VERSION 5.8 ;
BUSBITCHARS "[]" ;
DIVIDERCHAR "/" ;
UNITS
    DATABASE MICRONS 1000 ;
END UNITS

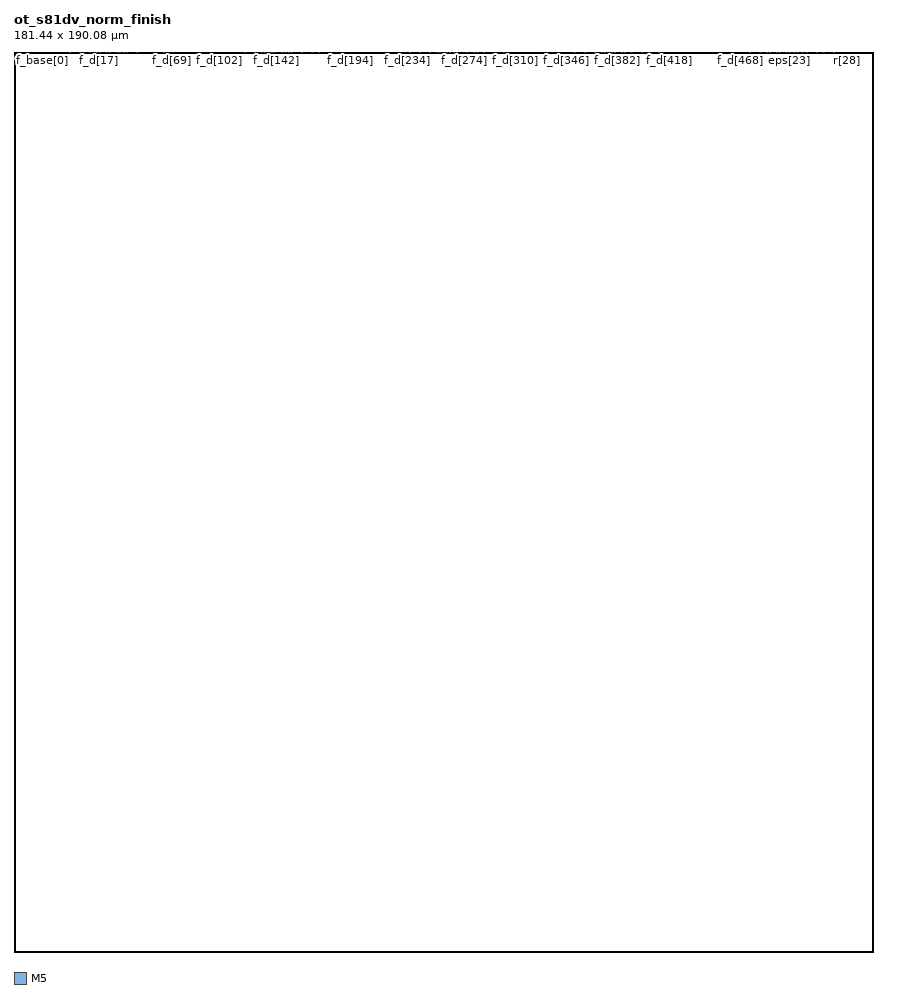
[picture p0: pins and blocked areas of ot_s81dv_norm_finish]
MACRO ot_s81dv_norm_finish
  FOREIGN ot_s81dv_norm_finish 0 0 ;
  CLASS BLOCK ;
  SIZE 181.44 BY 190.08 ;
  PIN go
    DIRECTION INPUT ;
    USE SIGNAL ;
    PORT
      LAYER M5 ;
        RECT 4.3200 189.9960 4.3440 190.0800 ;
    END
  END go
  PIN f_v[0]
    DIRECTION INPUT ;
    USE SIGNAL ;
    PORT
      LAYER M5 ;
        RECT 4.6080 189.9960 4.6320 190.0800 ;
    END
  END f_v[0]
  PIN f_v[1]
    DIRECTION INPUT ;
    USE SIGNAL ;
    PORT
      LAYER M5 ;
        RECT 4.9440 189.9960 4.9680 190.0800 ;
    END
  END f_v[1]
  PIN f_v[2]
    DIRECTION INPUT ;
    USE SIGNAL ;
    PORT
      LAYER M5 ;
        RECT 5.2320 189.9960 5.2560 190.0800 ;
    END
  END f_v[2]
  PIN f_base[0]
    DIRECTION INPUT ;
    USE SIGNAL ;
    PORT
      LAYER M5 ;
        RECT 5.5200 189.9960 5.5440 190.0800 ;
    END
  END f_base[0]
  PIN f_base[1]
    DIRECTION INPUT ;
    USE SIGNAL ;
    PORT
      LAYER M5 ;
        RECT 5.8080 189.9960 5.8320 190.0800 ;
    END
  END f_base[1]
  PIN f_base[2]
    DIRECTION INPUT ;
    USE SIGNAL ;
    PORT
      LAYER M5 ;
        RECT 6.1440 189.9960 6.1680 190.0800 ;
    END
  END f_base[2]
  PIN f_base[3]
    DIRECTION INPUT ;
    USE SIGNAL ;
    PORT
      LAYER M5 ;
        RECT 6.4320 189.9960 6.4560 190.0800 ;
    END
  END f_base[3]
  PIN f_base[4]
    DIRECTION INPUT ;
    USE SIGNAL ;
    PORT
      LAYER M5 ;
        RECT 6.7200 189.9960 6.7440 190.0800 ;
    END
  END f_base[4]
  PIN f_base[5]
    DIRECTION INPUT ;
    USE SIGNAL ;
    PORT
      LAYER M5 ;
        RECT 7.0080 189.9960 7.0320 190.0800 ;
    END
  END f_base[5]
  PIN f_base[6]
    DIRECTION INPUT ;
    USE SIGNAL ;
    PORT
      LAYER M5 ;
        RECT 7.3440 189.9960 7.3680 190.0800 ;
    END
  END f_base[6]
  PIN f_base[7]
    DIRECTION INPUT ;
    USE SIGNAL ;
    PORT
      LAYER M5 ;
        RECT 7.6320 189.9960 7.6560 190.0800 ;
    END
  END f_base[7]
  PIN f_base[8]
    DIRECTION INPUT ;
    USE SIGNAL ;
    PORT
      LAYER M5 ;
        RECT 7.9200 189.9960 7.9440 190.0800 ;
    END
  END f_base[8]
  PIN f_base[9]
    DIRECTION INPUT ;
    USE SIGNAL ;
    PORT
      LAYER M5 ;
        RECT 8.2080 189.9960 8.2320 190.0800 ;
    END
  END f_base[9]
  PIN f_base[10]
    DIRECTION INPUT ;
    USE SIGNAL ;
    PORT
      LAYER M5 ;
        RECT 8.5440 189.9960 8.5680 190.0800 ;
    END
  END f_base[10]
  PIN f_base[11]
    DIRECTION INPUT ;
    USE SIGNAL ;
    PORT
      LAYER M5 ;
        RECT 8.8320 189.9960 8.8560 190.0800 ;
    END
  END f_base[11]
  PIN f_base[12]
    DIRECTION INPUT ;
    USE SIGNAL ;
    PORT
      LAYER M5 ;
        RECT 9.1200 189.9960 9.1440 190.0800 ;
    END
  END f_base[12]
  PIN f_base[13]
    DIRECTION INPUT ;
    USE SIGNAL ;
    PORT
      LAYER M5 ;
        RECT 9.4080 189.9960 9.4320 190.0800 ;
    END
  END f_base[13]
  PIN f_base[14]
    DIRECTION INPUT ;
    USE SIGNAL ;
    PORT
      LAYER M5 ;
        RECT 9.7440 189.9960 9.7680 190.0800 ;
    END
  END f_base[14]
  PIN f_base[15]
    DIRECTION INPUT ;
    USE SIGNAL ;
    PORT
      LAYER M5 ;
        RECT 10.0320 189.9960 10.0560 190.0800 ;
    END
  END f_base[15]
  PIN f_base[16]
    DIRECTION INPUT ;
    USE SIGNAL ;
    PORT
      LAYER M5 ;
        RECT 10.3200 189.9960 10.3440 190.0800 ;
    END
  END f_base[16]
  PIN f_base[17]
    DIRECTION INPUT ;
    USE SIGNAL ;
    PORT
      LAYER M5 ;
        RECT 10.6080 189.9960 10.6320 190.0800 ;
    END
  END f_base[17]
  PIN f_base[18]
    DIRECTION INPUT ;
    USE SIGNAL ;
    PORT
      LAYER M5 ;
        RECT 10.9440 189.9960 10.9680 190.0800 ;
    END
  END f_base[18]
  PIN f_base[19]
    DIRECTION INPUT ;
    USE SIGNAL ;
    PORT
      LAYER M5 ;
        RECT 11.2320 189.9960 11.2560 190.0800 ;
    END
  END f_base[19]
  PIN f_base[20]
    DIRECTION INPUT ;
    USE SIGNAL ;
    PORT
      LAYER M5 ;
        RECT 11.5200 189.9960 11.5440 190.0800 ;
    END
  END f_base[20]
  PIN f_base[21]
    DIRECTION INPUT ;
    USE SIGNAL ;
    PORT
      LAYER M5 ;
        RECT 11.8080 189.9960 11.8320 190.0800 ;
    END
  END f_base[21]
  PIN f_base[22]
    DIRECTION INPUT ;
    USE SIGNAL ;
    PORT
      LAYER M5 ;
        RECT 12.1440 189.9960 12.1680 190.0800 ;
    END
  END f_base[22]
  PIN f_base[23]
    DIRECTION INPUT ;
    USE SIGNAL ;
    PORT
      LAYER M5 ;
        RECT 12.4320 189.9960 12.4560 190.0800 ;
    END
  END f_base[23]
  PIN f_d[0]
    DIRECTION INPUT ;
    USE SIGNAL ;
    PORT
      LAYER M5 ;
        RECT 12.7200 189.9960 12.7440 190.0800 ;
    END
  END f_d[0]
  PIN f_d[1]
    DIRECTION INPUT ;
    USE SIGNAL ;
    PORT
      LAYER M5 ;
        RECT 13.0560 189.9960 13.0800 190.0800 ;
    END
  END f_d[1]
  PIN f_d[2]
    DIRECTION INPUT ;
    USE SIGNAL ;
    PORT
      LAYER M5 ;
        RECT 13.3440 189.9960 13.3680 190.0800 ;
    END
  END f_d[2]
  PIN f_d[3]
    DIRECTION INPUT ;
    USE SIGNAL ;
    PORT
      LAYER M5 ;
        RECT 13.6320 189.9960 13.6560 190.0800 ;
    END
  END f_d[3]
  PIN f_d[4]
    DIRECTION INPUT ;
    USE SIGNAL ;
    PORT
      LAYER M5 ;
        RECT 13.9200 189.9960 13.9440 190.0800 ;
    END
  END f_d[4]
  PIN f_d[5]
    DIRECTION INPUT ;
    USE SIGNAL ;
    PORT
      LAYER M5 ;
        RECT 14.2560 189.9960 14.2800 190.0800 ;
    END
  END f_d[5]
  PIN f_d[6]
    DIRECTION INPUT ;
    USE SIGNAL ;
    PORT
      LAYER M5 ;
        RECT 14.5440 189.9960 14.5680 190.0800 ;
    END
  END f_d[6]
  PIN f_d[7]
    DIRECTION INPUT ;
    USE SIGNAL ;
    PORT
      LAYER M5 ;
        RECT 14.8320 189.9960 14.8560 190.0800 ;
    END
  END f_d[7]
  PIN f_d[8]
    DIRECTION INPUT ;
    USE SIGNAL ;
    PORT
      LAYER M5 ;
        RECT 15.1200 189.9960 15.1440 190.0800 ;
    END
  END f_d[8]
  PIN f_d[9]
    DIRECTION INPUT ;
    USE SIGNAL ;
    PORT
      LAYER M5 ;
        RECT 15.4560 189.9960 15.4800 190.0800 ;
    END
  END f_d[9]
  PIN f_d[10]
    DIRECTION INPUT ;
    USE SIGNAL ;
    PORT
      LAYER M5 ;
        RECT 15.7440 189.9960 15.7680 190.0800 ;
    END
  END f_d[10]
  PIN f_d[11]
    DIRECTION INPUT ;
    USE SIGNAL ;
    PORT
      LAYER M5 ;
        RECT 16.0320 189.9960 16.0560 190.0800 ;
    END
  END f_d[11]
  PIN f_d[12]
    DIRECTION INPUT ;
    USE SIGNAL ;
    PORT
      LAYER M5 ;
        RECT 16.3200 189.9960 16.3440 190.0800 ;
    END
  END f_d[12]
  PIN f_d[13]
    DIRECTION INPUT ;
    USE SIGNAL ;
    PORT
      LAYER M5 ;
        RECT 16.6560 189.9960 16.6800 190.0800 ;
    END
  END f_d[13]
  PIN f_d[14]
    DIRECTION INPUT ;
    USE SIGNAL ;
    PORT
      LAYER M5 ;
        RECT 16.9440 189.9960 16.9680 190.0800 ;
    END
  END f_d[14]
  PIN f_d[15]
    DIRECTION INPUT ;
    USE SIGNAL ;
    PORT
      LAYER M5 ;
        RECT 17.2320 189.9960 17.2560 190.0800 ;
    END
  END f_d[15]
  PIN f_d[16]
    DIRECTION INPUT ;
    USE SIGNAL ;
    PORT
      LAYER M5 ;
        RECT 17.5200 189.9960 17.5440 190.0800 ;
    END
  END f_d[16]
  PIN f_d[17]
    DIRECTION INPUT ;
    USE SIGNAL ;
    PORT
      LAYER M5 ;
        RECT 17.8560 189.9960 17.8800 190.0800 ;
    END
  END f_d[17]
  PIN f_d[18]
    DIRECTION INPUT ;
    USE SIGNAL ;
    PORT
      LAYER M5 ;
        RECT 18.1440 189.9960 18.1680 190.0800 ;
    END
  END f_d[18]
  PIN f_d[19]
    DIRECTION INPUT ;
    USE SIGNAL ;
    PORT
      LAYER M5 ;
        RECT 18.4320 189.9960 18.4560 190.0800 ;
    END
  END f_d[19]
  PIN f_d[20]
    DIRECTION INPUT ;
    USE SIGNAL ;
    PORT
      LAYER M5 ;
        RECT 18.7200 189.9960 18.7440 190.0800 ;
    END
  END f_d[20]
  PIN f_d[21]
    DIRECTION INPUT ;
    USE SIGNAL ;
    PORT
      LAYER M5 ;
        RECT 19.0560 189.9960 19.0800 190.0800 ;
    END
  END f_d[21]
  PIN f_d[22]
    DIRECTION INPUT ;
    USE SIGNAL ;
    PORT
      LAYER M5 ;
        RECT 19.3440 189.9960 19.3680 190.0800 ;
    END
  END f_d[22]
  PIN f_d[23]
    DIRECTION INPUT ;
    USE SIGNAL ;
    PORT
      LAYER M5 ;
        RECT 19.6320 189.9960 19.6560 190.0800 ;
    END
  END f_d[23]
  PIN f_d[24]
    DIRECTION INPUT ;
    USE SIGNAL ;
    PORT
      LAYER M5 ;
        RECT 19.9200 189.9960 19.9440 190.0800 ;
    END
  END f_d[24]
  PIN f_d[25]
    DIRECTION INPUT ;
    USE SIGNAL ;
    PORT
      LAYER M5 ;
        RECT 20.2560 189.9960 20.2800 190.0800 ;
    END
  END f_d[25]
  PIN f_d[26]
    DIRECTION INPUT ;
    USE SIGNAL ;
    PORT
      LAYER M5 ;
        RECT 20.5440 189.9960 20.5680 190.0800 ;
    END
  END f_d[26]
  PIN f_d[27]
    DIRECTION INPUT ;
    USE SIGNAL ;
    PORT
      LAYER M5 ;
        RECT 20.8320 189.9960 20.8560 190.0800 ;
    END
  END f_d[27]
  PIN f_d[28]
    DIRECTION INPUT ;
    USE SIGNAL ;
    PORT
      LAYER M5 ;
        RECT 21.1680 189.9960 21.1920 190.0800 ;
    END
  END f_d[28]
  PIN f_d[29]
    DIRECTION INPUT ;
    USE SIGNAL ;
    PORT
      LAYER M5 ;
        RECT 21.4560 189.9960 21.4800 190.0800 ;
    END
  END f_d[29]
  PIN f_d[30]
    DIRECTION INPUT ;
    USE SIGNAL ;
    PORT
      LAYER M5 ;
        RECT 21.7440 189.9960 21.7680 190.0800 ;
    END
  END f_d[30]
  PIN f_d[31]
    DIRECTION INPUT ;
    USE SIGNAL ;
    PORT
      LAYER M5 ;
        RECT 22.0320 189.9960 22.0560 190.0800 ;
    END
  END f_d[31]
  PIN f_d[32]
    DIRECTION INPUT ;
    USE SIGNAL ;
    PORT
      LAYER M5 ;
        RECT 22.3680 189.9960 22.3920 190.0800 ;
    END
  END f_d[32]
  PIN f_d[33]
    DIRECTION INPUT ;
    USE SIGNAL ;
    PORT
      LAYER M5 ;
        RECT 22.6560 189.9960 22.6800 190.0800 ;
    END
  END f_d[33]
  PIN f_d[34]
    DIRECTION INPUT ;
    USE SIGNAL ;
    PORT
      LAYER M5 ;
        RECT 22.9440 189.9960 22.9680 190.0800 ;
    END
  END f_d[34]
  PIN f_d[35]
    DIRECTION INPUT ;
    USE SIGNAL ;
    PORT
      LAYER M5 ;
        RECT 23.2320 189.9960 23.2560 190.0800 ;
    END
  END f_d[35]
  PIN f_d[36]
    DIRECTION INPUT ;
    USE SIGNAL ;
    PORT
      LAYER M5 ;
        RECT 23.5680 189.9960 23.5920 190.0800 ;
    END
  END f_d[36]
  PIN f_d[37]
    DIRECTION INPUT ;
    USE SIGNAL ;
    PORT
      LAYER M5 ;
        RECT 23.8560 189.9960 23.8800 190.0800 ;
    END
  END f_d[37]
  PIN f_d[38]
    DIRECTION INPUT ;
    USE SIGNAL ;
    PORT
      LAYER M5 ;
        RECT 24.1440 189.9960 24.1680 190.0800 ;
    END
  END f_d[38]
  PIN f_d[39]
    DIRECTION INPUT ;
    USE SIGNAL ;
    PORT
      LAYER M5 ;
        RECT 24.4320 189.9960 24.4560 190.0800 ;
    END
  END f_d[39]
  PIN f_d[40]
    DIRECTION INPUT ;
    USE SIGNAL ;
    PORT
      LAYER M5 ;
        RECT 24.7680 189.9960 24.7920 190.0800 ;
    END
  END f_d[40]
  PIN f_d[41]
    DIRECTION INPUT ;
    USE SIGNAL ;
    PORT
      LAYER M5 ;
        RECT 25.0560 189.9960 25.0800 190.0800 ;
    END
  END f_d[41]
  PIN f_d[42]
    DIRECTION INPUT ;
    USE SIGNAL ;
    PORT
      LAYER M5 ;
        RECT 25.3440 189.9960 25.3680 190.0800 ;
    END
  END f_d[42]
  PIN f_d[43]
    DIRECTION INPUT ;
    USE SIGNAL ;
    PORT
      LAYER M5 ;
        RECT 25.6320 189.9960 25.6560 190.0800 ;
    END
  END f_d[43]
  PIN f_d[44]
    DIRECTION INPUT ;
    USE SIGNAL ;
    PORT
      LAYER M5 ;
        RECT 25.9680 189.9960 25.9920 190.0800 ;
    END
  END f_d[44]
  PIN f_d[45]
    DIRECTION INPUT ;
    USE SIGNAL ;
    PORT
      LAYER M5 ;
        RECT 26.2560 189.9960 26.2800 190.0800 ;
    END
  END f_d[45]
  PIN f_d[46]
    DIRECTION INPUT ;
    USE SIGNAL ;
    PORT
      LAYER M5 ;
        RECT 26.5440 189.9960 26.5680 190.0800 ;
    END
  END f_d[46]
  PIN f_d[47]
    DIRECTION INPUT ;
    USE SIGNAL ;
    PORT
      LAYER M5 ;
        RECT 26.8320 189.9960 26.8560 190.0800 ;
    END
  END f_d[47]
  PIN f_d[48]
    DIRECTION INPUT ;
    USE SIGNAL ;
    PORT
      LAYER M5 ;
        RECT 27.1680 189.9960 27.1920 190.0800 ;
    END
  END f_d[48]
  PIN f_d[49]
    DIRECTION INPUT ;
    USE SIGNAL ;
    PORT
      LAYER M5 ;
        RECT 27.4560 189.9960 27.4800 190.0800 ;
    END
  END f_d[49]
  PIN f_d[50]
    DIRECTION INPUT ;
    USE SIGNAL ;
    PORT
      LAYER M5 ;
        RECT 27.7440 189.9960 27.7680 190.0800 ;
    END
  END f_d[50]
  PIN f_d[51]
    DIRECTION INPUT ;
    USE SIGNAL ;
    PORT
      LAYER M5 ;
        RECT 28.0320 189.9960 28.0560 190.0800 ;
    END
  END f_d[51]
  PIN f_d[52]
    DIRECTION INPUT ;
    USE SIGNAL ;
    PORT
      LAYER M5 ;
        RECT 28.3680 189.9960 28.3920 190.0800 ;
    END
  END f_d[52]
  PIN f_d[53]
    DIRECTION INPUT ;
    USE SIGNAL ;
    PORT
      LAYER M5 ;
        RECT 28.6560 189.9960 28.6800 190.0800 ;
    END
  END f_d[53]
  PIN f_d[54]
    DIRECTION INPUT ;
    USE SIGNAL ;
    PORT
      LAYER M5 ;
        RECT 28.9440 189.9960 28.9680 190.0800 ;
    END
  END f_d[54]
  PIN f_d[55]
    DIRECTION INPUT ;
    USE SIGNAL ;
    PORT
      LAYER M5 ;
        RECT 29.2800 189.9960 29.3040 190.0800 ;
    END
  END f_d[55]
  PIN f_d[56]
    DIRECTION INPUT ;
    USE SIGNAL ;
    PORT
      LAYER M5 ;
        RECT 29.5680 189.9960 29.5920 190.0800 ;
    END
  END f_d[56]
  PIN f_d[57]
    DIRECTION INPUT ;
    USE SIGNAL ;
    PORT
      LAYER M5 ;
        RECT 29.8560 189.9960 29.8800 190.0800 ;
    END
  END f_d[57]
  PIN f_d[58]
    DIRECTION INPUT ;
    USE SIGNAL ;
    PORT
      LAYER M5 ;
        RECT 30.1440 189.9960 30.1680 190.0800 ;
    END
  END f_d[58]
  PIN f_d[59]
    DIRECTION INPUT ;
    USE SIGNAL ;
    PORT
      LAYER M5 ;
        RECT 30.4800 189.9960 30.5040 190.0800 ;
    END
  END f_d[59]
  PIN f_d[60]
    DIRECTION INPUT ;
    USE SIGNAL ;
    PORT
      LAYER M5 ;
        RECT 30.7680 189.9960 30.7920 190.0800 ;
    END
  END f_d[60]
  PIN f_d[61]
    DIRECTION INPUT ;
    USE SIGNAL ;
    PORT
      LAYER M5 ;
        RECT 31.0560 189.9960 31.0800 190.0800 ;
    END
  END f_d[61]
  PIN f_d[62]
    DIRECTION INPUT ;
    USE SIGNAL ;
    PORT
      LAYER M5 ;
        RECT 31.3440 189.9960 31.3680 190.0800 ;
    END
  END f_d[62]
  PIN f_d[63]
    DIRECTION INPUT ;
    USE SIGNAL ;
    PORT
      LAYER M5 ;
        RECT 31.6800 189.9960 31.7040 190.0800 ;
    END
  END f_d[63]
  PIN f_d[64]
    DIRECTION INPUT ;
    USE SIGNAL ;
    PORT
      LAYER M5 ;
        RECT 31.9680 189.9960 31.9920 190.0800 ;
    END
  END f_d[64]
  PIN f_d[65]
    DIRECTION INPUT ;
    USE SIGNAL ;
    PORT
      LAYER M5 ;
        RECT 32.2560 189.9960 32.2800 190.0800 ;
    END
  END f_d[65]
  PIN f_d[66]
    DIRECTION INPUT ;
    USE SIGNAL ;
    PORT
      LAYER M5 ;
        RECT 32.5440 189.9960 32.5680 190.0800 ;
    END
  END f_d[66]
  PIN f_d[67]
    DIRECTION INPUT ;
    USE SIGNAL ;
    PORT
      LAYER M5 ;
        RECT 32.8800 189.9960 32.9040 190.0800 ;
    END
  END f_d[67]
  PIN f_d[68]
    DIRECTION INPUT ;
    USE SIGNAL ;
    PORT
      LAYER M5 ;
        RECT 33.1680 189.9960 33.1920 190.0800 ;
    END
  END f_d[68]
  PIN f_d[69]
    DIRECTION INPUT ;
    USE SIGNAL ;
    PORT
      LAYER M5 ;
        RECT 33.4560 189.9960 33.4800 190.0800 ;
    END
  END f_d[69]
  PIN f_d[70]
    DIRECTION INPUT ;
    USE SIGNAL ;
    PORT
      LAYER M5 ;
        RECT 33.7440 189.9960 33.7680 190.0800 ;
    END
  END f_d[70]
  PIN f_d[71]
    DIRECTION INPUT ;
    USE SIGNAL ;
    PORT
      LAYER M5 ;
        RECT 34.0800 189.9960 34.1040 190.0800 ;
    END
  END f_d[71]
  PIN f_d[72]
    DIRECTION INPUT ;
    USE SIGNAL ;
    PORT
      LAYER M5 ;
        RECT 34.3680 189.9960 34.3920 190.0800 ;
    END
  END f_d[72]
  PIN f_d[73]
    DIRECTION INPUT ;
    USE SIGNAL ;
    PORT
      LAYER M5 ;
        RECT 34.6560 189.9960 34.6800 190.0800 ;
    END
  END f_d[73]
  PIN f_d[74]
    DIRECTION INPUT ;
    USE SIGNAL ;
    PORT
      LAYER M5 ;
        RECT 34.9440 189.9960 34.9680 190.0800 ;
    END
  END f_d[74]
  PIN f_d[75]
    DIRECTION INPUT ;
    USE SIGNAL ;
    PORT
      LAYER M5 ;
        RECT 35.2800 189.9960 35.3040 190.0800 ;
    END
  END f_d[75]
  PIN f_d[76]
    DIRECTION INPUT ;
    USE SIGNAL ;
    PORT
      LAYER M5 ;
        RECT 35.5680 189.9960 35.5920 190.0800 ;
    END
  END f_d[76]
  PIN f_d[77]
    DIRECTION INPUT ;
    USE SIGNAL ;
    PORT
      LAYER M5 ;
        RECT 35.8560 189.9960 35.8800 190.0800 ;
    END
  END f_d[77]
  PIN f_d[78]
    DIRECTION INPUT ;
    USE SIGNAL ;
    PORT
      LAYER M5 ;
        RECT 36.1440 189.9960 36.1680 190.0800 ;
    END
  END f_d[78]
  PIN f_d[79]
    DIRECTION INPUT ;
    USE SIGNAL ;
    PORT
      LAYER M5 ;
        RECT 36.4800 189.9960 36.5040 190.0800 ;
    END
  END f_d[79]
  PIN f_d[80]
    DIRECTION INPUT ;
    USE SIGNAL ;
    PORT
      LAYER M5 ;
        RECT 36.7680 189.9960 36.7920 190.0800 ;
    END
  END f_d[80]
  PIN f_d[81]
    DIRECTION INPUT ;
    USE SIGNAL ;
    PORT
      LAYER M5 ;
        RECT 37.0560 189.9960 37.0800 190.0800 ;
    END
  END f_d[81]
  PIN f_d[82]
    DIRECTION INPUT ;
    USE SIGNAL ;
    PORT
      LAYER M5 ;
        RECT 37.3920 189.9960 37.4160 190.0800 ;
    END
  END f_d[82]
  PIN f_d[83]
    DIRECTION INPUT ;
    USE SIGNAL ;
    PORT
      LAYER M5 ;
        RECT 37.6800 189.9960 37.7040 190.0800 ;
    END
  END f_d[83]
  PIN f_d[84]
    DIRECTION INPUT ;
    USE SIGNAL ;
    PORT
      LAYER M5 ;
        RECT 37.9680 189.9960 37.9920 190.0800 ;
    END
  END f_d[84]
  PIN f_d[85]
    DIRECTION INPUT ;
    USE SIGNAL ;
    PORT
      LAYER M5 ;
        RECT 38.2560 189.9960 38.2800 190.0800 ;
    END
  END f_d[85]
  PIN f_d[86]
    DIRECTION INPUT ;
    USE SIGNAL ;
    PORT
      LAYER M5 ;
        RECT 38.5920 189.9960 38.6160 190.0800 ;
    END
  END f_d[86]
  PIN f_d[87]
    DIRECTION INPUT ;
    USE SIGNAL ;
    PORT
      LAYER M5 ;
        RECT 38.8800 189.9960 38.9040 190.0800 ;
    END
  END f_d[87]
  PIN f_d[88]
    DIRECTION INPUT ;
    USE SIGNAL ;
    PORT
      LAYER M5 ;
        RECT 39.1680 189.9960 39.1920 190.0800 ;
    END
  END f_d[88]
  PIN f_d[89]
    DIRECTION INPUT ;
    USE SIGNAL ;
    PORT
      LAYER M5 ;
        RECT 39.4560 189.9960 39.4800 190.0800 ;
    END
  END f_d[89]
  PIN f_d[90]
    DIRECTION INPUT ;
    USE SIGNAL ;
    PORT
      LAYER M5 ;
        RECT 39.7920 189.9960 39.8160 190.0800 ;
    END
  END f_d[90]
  PIN f_d[91]
    DIRECTION INPUT ;
    USE SIGNAL ;
    PORT
      LAYER M5 ;
        RECT 40.0800 189.9960 40.1040 190.0800 ;
    END
  END f_d[91]
  PIN f_d[92]
    DIRECTION INPUT ;
    USE SIGNAL ;
    PORT
      LAYER M5 ;
        RECT 40.3680 189.9960 40.3920 190.0800 ;
    END
  END f_d[92]
  PIN f_d[93]
    DIRECTION INPUT ;
    USE SIGNAL ;
    PORT
      LAYER M5 ;
        RECT 40.6560 189.9960 40.6800 190.0800 ;
    END
  END f_d[93]
  PIN f_d[94]
    DIRECTION INPUT ;
    USE SIGNAL ;
    PORT
      LAYER M5 ;
        RECT 40.9920 189.9960 41.0160 190.0800 ;
    END
  END f_d[94]
  PIN f_d[95]
    DIRECTION INPUT ;
    USE SIGNAL ;
    PORT
      LAYER M5 ;
        RECT 41.2800 189.9960 41.3040 190.0800 ;
    END
  END f_d[95]
  PIN f_d[96]
    DIRECTION INPUT ;
    USE SIGNAL ;
    PORT
      LAYER M5 ;
        RECT 41.5680 189.9960 41.5920 190.0800 ;
    END
  END f_d[96]
  PIN f_d[97]
    DIRECTION INPUT ;
    USE SIGNAL ;
    PORT
      LAYER M5 ;
        RECT 41.8560 189.9960 41.8800 190.0800 ;
    END
  END f_d[97]
  PIN f_d[98]
    DIRECTION INPUT ;
    USE SIGNAL ;
    PORT
      LAYER M5 ;
        RECT 42.1920 189.9960 42.2160 190.0800 ;
    END
  END f_d[98]
  PIN f_d[99]
    DIRECTION INPUT ;
    USE SIGNAL ;
    PORT
      LAYER M5 ;
        RECT 42.4800 189.9960 42.5040 190.0800 ;
    END
  END f_d[99]
  PIN f_d[100]
    DIRECTION INPUT ;
    USE SIGNAL ;
    PORT
      LAYER M5 ;
        RECT 42.7680 189.9960 42.7920 190.0800 ;
    END
  END f_d[100]
  PIN f_d[101]
    DIRECTION INPUT ;
    USE SIGNAL ;
    PORT
      LAYER M5 ;
        RECT 43.0560 189.9960 43.0800 190.0800 ;
    END
  END f_d[101]
  PIN f_d[102]
    DIRECTION INPUT ;
    USE SIGNAL ;
    PORT
      LAYER M5 ;
        RECT 43.3920 189.9960 43.4160 190.0800 ;
    END
  END f_d[102]
  PIN f_d[103]
    DIRECTION INPUT ;
    USE SIGNAL ;
    PORT
      LAYER M5 ;
        RECT 43.6800 189.9960 43.7040 190.0800 ;
    END
  END f_d[103]
  PIN f_d[104]
    DIRECTION INPUT ;
    USE SIGNAL ;
    PORT
      LAYER M5 ;
        RECT 43.9680 189.9960 43.9920 190.0800 ;
    END
  END f_d[104]
  PIN f_d[105]
    DIRECTION INPUT ;
    USE SIGNAL ;
    PORT
      LAYER M5 ;
        RECT 44.2560 189.9960 44.2800 190.0800 ;
    END
  END f_d[105]
  PIN f_d[106]
    DIRECTION INPUT ;
    USE SIGNAL ;
    PORT
      LAYER M5 ;
        RECT 44.5920 189.9960 44.6160 190.0800 ;
    END
  END f_d[106]
  PIN f_d[107]
    DIRECTION INPUT ;
    USE SIGNAL ;
    PORT
      LAYER M5 ;
        RECT 44.8800 189.9960 44.9040 190.0800 ;
    END
  END f_d[107]
  PIN f_d[108]
    DIRECTION INPUT ;
    USE SIGNAL ;
    PORT
      LAYER M5 ;
        RECT 45.1680 189.9960 45.1920 190.0800 ;
    END
  END f_d[108]
  PIN f_d[109]
    DIRECTION INPUT ;
    USE SIGNAL ;
    PORT
      LAYER M5 ;
        RECT 45.5040 189.9960 45.5280 190.0800 ;
    END
  END f_d[109]
  PIN f_d[110]
    DIRECTION INPUT ;
    USE SIGNAL ;
    PORT
      LAYER M5 ;
        RECT 45.7920 189.9960 45.8160 190.0800 ;
    END
  END f_d[110]
  PIN f_d[111]
    DIRECTION INPUT ;
    USE SIGNAL ;
    PORT
      LAYER M5 ;
        RECT 46.0800 189.9960 46.1040 190.0800 ;
    END
  END f_d[111]
  PIN f_d[112]
    DIRECTION INPUT ;
    USE SIGNAL ;
    PORT
      LAYER M5 ;
        RECT 46.3680 189.9960 46.3920 190.0800 ;
    END
  END f_d[112]
  PIN f_d[113]
    DIRECTION INPUT ;
    USE SIGNAL ;
    PORT
      LAYER M5 ;
        RECT 46.7040 189.9960 46.7280 190.0800 ;
    END
  END f_d[113]
  PIN f_d[114]
    DIRECTION INPUT ;
    USE SIGNAL ;
    PORT
      LAYER M5 ;
        RECT 46.9920 189.9960 47.0160 190.0800 ;
    END
  END f_d[114]
  PIN f_d[115]
    DIRECTION INPUT ;
    USE SIGNAL ;
    PORT
      LAYER M5 ;
        RECT 47.2800 189.9960 47.3040 190.0800 ;
    END
  END f_d[115]
  PIN f_d[116]
    DIRECTION INPUT ;
    USE SIGNAL ;
    PORT
      LAYER M5 ;
        RECT 47.5680 189.9960 47.5920 190.0800 ;
    END
  END f_d[116]
  PIN f_d[117]
    DIRECTION INPUT ;
    USE SIGNAL ;
    PORT
      LAYER M5 ;
        RECT 47.9040 189.9960 47.9280 190.0800 ;
    END
  END f_d[117]
  PIN f_d[118]
    DIRECTION INPUT ;
    USE SIGNAL ;
    PORT
      LAYER M5 ;
        RECT 48.1920 189.9960 48.2160 190.0800 ;
    END
  END f_d[118]
  PIN f_d[119]
    DIRECTION INPUT ;
    USE SIGNAL ;
    PORT
      LAYER M5 ;
        RECT 48.4800 189.9960 48.5040 190.0800 ;
    END
  END f_d[119]
  PIN f_d[120]
    DIRECTION INPUT ;
    USE SIGNAL ;
    PORT
      LAYER M5 ;
        RECT 48.7680 189.9960 48.7920 190.0800 ;
    END
  END f_d[120]
  PIN f_d[121]
    DIRECTION INPUT ;
    USE SIGNAL ;
    PORT
      LAYER M5 ;
        RECT 49.1040 189.9960 49.1280 190.0800 ;
    END
  END f_d[121]
  PIN f_d[122]
    DIRECTION INPUT ;
    USE SIGNAL ;
    PORT
      LAYER M5 ;
        RECT 49.3920 189.9960 49.4160 190.0800 ;
    END
  END f_d[122]
  PIN f_d[123]
    DIRECTION INPUT ;
    USE SIGNAL ;
    PORT
      LAYER M5 ;
        RECT 49.6800 189.9960 49.7040 190.0800 ;
    END
  END f_d[123]
  PIN f_d[124]
    DIRECTION INPUT ;
    USE SIGNAL ;
    PORT
      LAYER M5 ;
        RECT 49.9680 189.9960 49.9920 190.0800 ;
    END
  END f_d[124]
  PIN f_d[125]
    DIRECTION INPUT ;
    USE SIGNAL ;
    PORT
      LAYER M5 ;
        RECT 50.3040 189.9960 50.3280 190.0800 ;
    END
  END f_d[125]
  PIN f_d[126]
    DIRECTION INPUT ;
    USE SIGNAL ;
    PORT
      LAYER M5 ;
        RECT 50.5920 189.9960 50.6160 190.0800 ;
    END
  END f_d[126]
  PIN f_d[127]
    DIRECTION INPUT ;
    USE SIGNAL ;
    PORT
      LAYER M5 ;
        RECT 50.8800 189.9960 50.9040 190.0800 ;
    END
  END f_d[127]
  PIN f_d[128]
    DIRECTION INPUT ;
    USE SIGNAL ;
    PORT
      LAYER M5 ;
        RECT 51.1680 189.9960 51.1920 190.0800 ;
    END
  END f_d[128]
  PIN f_d[129]
    DIRECTION INPUT ;
    USE SIGNAL ;
    PORT
      LAYER M5 ;
        RECT 51.5040 189.9960 51.5280 190.0800 ;
    END
  END f_d[129]
  PIN f_d[130]
    DIRECTION INPUT ;
    USE SIGNAL ;
    PORT
      LAYER M5 ;
        RECT 51.7920 189.9960 51.8160 190.0800 ;
    END
  END f_d[130]
  PIN f_d[131]
    DIRECTION INPUT ;
    USE SIGNAL ;
    PORT
      LAYER M5 ;
        RECT 52.0800 189.9960 52.1040 190.0800 ;
    END
  END f_d[131]
  PIN f_d[132]
    DIRECTION INPUT ;
    USE SIGNAL ;
    PORT
      LAYER M5 ;
        RECT 52.3680 189.9960 52.3920 190.0800 ;
    END
  END f_d[132]
  PIN f_d[133]
    DIRECTION INPUT ;
    USE SIGNAL ;
    PORT
      LAYER M5 ;
        RECT 52.7040 189.9960 52.7280 190.0800 ;
    END
  END f_d[133]
  PIN f_d[134]
    DIRECTION INPUT ;
    USE SIGNAL ;
    PORT
      LAYER M5 ;
        RECT 52.9920 189.9960 53.0160 190.0800 ;
    END
  END f_d[134]
  PIN f_d[135]
    DIRECTION INPUT ;
    USE SIGNAL ;
    PORT
      LAYER M5 ;
        RECT 53.2800 189.9960 53.3040 190.0800 ;
    END
  END f_d[135]
  PIN f_d[136]
    DIRECTION INPUT ;
    USE SIGNAL ;
    PORT
      LAYER M5 ;
        RECT 53.5680 189.9960 53.5920 190.0800 ;
    END
  END f_d[136]
  PIN f_d[137]
    DIRECTION INPUT ;
    USE SIGNAL ;
    PORT
      LAYER M5 ;
        RECT 53.9040 189.9960 53.9280 190.0800 ;
    END
  END f_d[137]
  PIN f_d[138]
    DIRECTION INPUT ;
    USE SIGNAL ;
    PORT
      LAYER M5 ;
        RECT 54.1920 189.9960 54.2160 190.0800 ;
    END
  END f_d[138]
  PIN f_d[139]
    DIRECTION INPUT ;
    USE SIGNAL ;
    PORT
      LAYER M5 ;
        RECT 54.4800 189.9960 54.5040 190.0800 ;
    END
  END f_d[139]
  PIN f_d[140]
    DIRECTION INPUT ;
    USE SIGNAL ;
    PORT
      LAYER M5 ;
        RECT 54.8160 189.9960 54.8400 190.0800 ;
    END
  END f_d[140]
  PIN f_d[141]
    DIRECTION INPUT ;
    USE SIGNAL ;
    PORT
      LAYER M5 ;
        RECT 55.1040 189.9960 55.1280 190.0800 ;
    END
  END f_d[141]
  PIN f_d[142]
    DIRECTION INPUT ;
    USE SIGNAL ;
    PORT
      LAYER M5 ;
        RECT 55.3920 189.9960 55.4160 190.0800 ;
    END
  END f_d[142]
  PIN f_d[143]
    DIRECTION INPUT ;
    USE SIGNAL ;
    PORT
      LAYER M5 ;
        RECT 55.6800 189.9960 55.7040 190.0800 ;
    END
  END f_d[143]
  PIN f_d[144]
    DIRECTION INPUT ;
    USE SIGNAL ;
    PORT
      LAYER M5 ;
        RECT 56.0160 189.9960 56.0400 190.0800 ;
    END
  END f_d[144]
  PIN f_d[145]
    DIRECTION INPUT ;
    USE SIGNAL ;
    PORT
      LAYER M5 ;
        RECT 56.3040 189.9960 56.3280 190.0800 ;
    END
  END f_d[145]
  PIN f_d[146]
    DIRECTION INPUT ;
    USE SIGNAL ;
    PORT
      LAYER M5 ;
        RECT 56.5920 189.9960 56.6160 190.0800 ;
    END
  END f_d[146]
  PIN f_d[147]
    DIRECTION INPUT ;
    USE SIGNAL ;
    PORT
      LAYER M5 ;
        RECT 56.8800 189.9960 56.9040 190.0800 ;
    END
  END f_d[147]
  PIN f_d[148]
    DIRECTION INPUT ;
    USE SIGNAL ;
    PORT
      LAYER M5 ;
        RECT 57.2160 189.9960 57.2400 190.0800 ;
    END
  END f_d[148]
  PIN f_d[149]
    DIRECTION INPUT ;
    USE SIGNAL ;
    PORT
      LAYER M5 ;
        RECT 57.5040 189.9960 57.5280 190.0800 ;
    END
  END f_d[149]
  PIN f_d[150]
    DIRECTION INPUT ;
    USE SIGNAL ;
    PORT
      LAYER M5 ;
        RECT 57.7920 189.9960 57.8160 190.0800 ;
    END
  END f_d[150]
  PIN f_d[151]
    DIRECTION INPUT ;
    USE SIGNAL ;
    PORT
      LAYER M5 ;
        RECT 58.0800 189.9960 58.1040 190.0800 ;
    END
  END f_d[151]
  PIN f_d[152]
    DIRECTION INPUT ;
    USE SIGNAL ;
    PORT
      LAYER M5 ;
        RECT 58.4160 189.9960 58.4400 190.0800 ;
    END
  END f_d[152]
  PIN f_d[153]
    DIRECTION INPUT ;
    USE SIGNAL ;
    PORT
      LAYER M5 ;
        RECT 58.7040 189.9960 58.7280 190.0800 ;
    END
  END f_d[153]
  PIN f_d[154]
    DIRECTION INPUT ;
    USE SIGNAL ;
    PORT
      LAYER M5 ;
        RECT 58.9920 189.9960 59.0160 190.0800 ;
    END
  END f_d[154]
  PIN f_d[155]
    DIRECTION INPUT ;
    USE SIGNAL ;
    PORT
      LAYER M5 ;
        RECT 59.2800 189.9960 59.3040 190.0800 ;
    END
  END f_d[155]
  PIN f_d[156]
    DIRECTION INPUT ;
    USE SIGNAL ;
    PORT
      LAYER M5 ;
        RECT 59.6160 189.9960 59.6400 190.0800 ;
    END
  END f_d[156]
  PIN f_d[157]
    DIRECTION INPUT ;
    USE SIGNAL ;
    PORT
      LAYER M5 ;
        RECT 59.9040 189.9960 59.9280 190.0800 ;
    END
  END f_d[157]
  PIN f_d[158]
    DIRECTION INPUT ;
    USE SIGNAL ;
    PORT
      LAYER M5 ;
        RECT 60.1920 189.9960 60.2160 190.0800 ;
    END
  END f_d[158]
  PIN f_d[159]
    DIRECTION INPUT ;
    USE SIGNAL ;
    PORT
      LAYER M5 ;
        RECT 60.4800 189.9960 60.5040 190.0800 ;
    END
  END f_d[159]
  PIN f_d[160]
    DIRECTION INPUT ;
    USE SIGNAL ;
    PORT
      LAYER M5 ;
        RECT 60.8160 189.9960 60.8400 190.0800 ;
    END
  END f_d[160]
  PIN f_d[161]
    DIRECTION INPUT ;
    USE SIGNAL ;
    PORT
      LAYER M5 ;
        RECT 61.1040 189.9960 61.1280 190.0800 ;
    END
  END f_d[161]
  PIN f_d[162]
    DIRECTION INPUT ;
    USE SIGNAL ;
    PORT
      LAYER M5 ;
        RECT 61.3920 189.9960 61.4160 190.0800 ;
    END
  END f_d[162]
  PIN f_d[163]
    DIRECTION INPUT ;
    USE SIGNAL ;
    PORT
      LAYER M5 ;
        RECT 61.6800 189.9960 61.7040 190.0800 ;
    END
  END f_d[163]
  PIN f_d[164]
    DIRECTION INPUT ;
    USE SIGNAL ;
    PORT
      LAYER M5 ;
        RECT 62.0160 189.9960 62.0400 190.0800 ;
    END
  END f_d[164]
  PIN f_d[165]
    DIRECTION INPUT ;
    USE SIGNAL ;
    PORT
      LAYER M5 ;
        RECT 62.3040 189.9960 62.3280 190.0800 ;
    END
  END f_d[165]
  PIN f_d[166]
    DIRECTION INPUT ;
    USE SIGNAL ;
    PORT
      LAYER M5 ;
        RECT 62.5920 189.9960 62.6160 190.0800 ;
    END
  END f_d[166]
  PIN f_d[167]
    DIRECTION INPUT ;
    USE SIGNAL ;
    PORT
      LAYER M5 ;
        RECT 62.9280 189.9960 62.9520 190.0800 ;
    END
  END f_d[167]
  PIN f_d[168]
    DIRECTION INPUT ;
    USE SIGNAL ;
    PORT
      LAYER M5 ;
        RECT 63.2160 189.9960 63.2400 190.0800 ;
    END
  END f_d[168]
  PIN f_d[169]
    DIRECTION INPUT ;
    USE SIGNAL ;
    PORT
      LAYER M5 ;
        RECT 63.5040 189.9960 63.5280 190.0800 ;
    END
  END f_d[169]
  PIN f_d[170]
    DIRECTION INPUT ;
    USE SIGNAL ;
    PORT
      LAYER M5 ;
        RECT 63.7920 189.9960 63.8160 190.0800 ;
    END
  END f_d[170]
  PIN f_d[171]
    DIRECTION INPUT ;
    USE SIGNAL ;
    PORT
      LAYER M5 ;
        RECT 64.1280 189.9960 64.1520 190.0800 ;
    END
  END f_d[171]
  PIN f_d[172]
    DIRECTION INPUT ;
    USE SIGNAL ;
    PORT
      LAYER M5 ;
        RECT 64.4160 189.9960 64.4400 190.0800 ;
    END
  END f_d[172]
  PIN f_d[173]
    DIRECTION INPUT ;
    USE SIGNAL ;
    PORT
      LAYER M5 ;
        RECT 64.7040 189.9960 64.7280 190.0800 ;
    END
  END f_d[173]
  PIN f_d[174]
    DIRECTION INPUT ;
    USE SIGNAL ;
    PORT
      LAYER M5 ;
        RECT 64.9920 189.9960 65.0160 190.0800 ;
    END
  END f_d[174]
  PIN f_d[175]
    DIRECTION INPUT ;
    USE SIGNAL ;
    PORT
      LAYER M5 ;
        RECT 65.3280 189.9960 65.3520 190.0800 ;
    END
  END f_d[175]
  PIN f_d[176]
    DIRECTION INPUT ;
    USE SIGNAL ;
    PORT
      LAYER M5 ;
        RECT 65.6160 189.9960 65.6400 190.0800 ;
    END
  END f_d[176]
  PIN f_d[177]
    DIRECTION INPUT ;
    USE SIGNAL ;
    PORT
      LAYER M5 ;
        RECT 65.9040 189.9960 65.9280 190.0800 ;
    END
  END f_d[177]
  PIN f_d[178]
    DIRECTION INPUT ;
    USE SIGNAL ;
    PORT
      LAYER M5 ;
        RECT 66.1920 189.9960 66.2160 190.0800 ;
    END
  END f_d[178]
  PIN f_d[179]
    DIRECTION INPUT ;
    USE SIGNAL ;
    PORT
      LAYER M5 ;
        RECT 66.5280 189.9960 66.5520 190.0800 ;
    END
  END f_d[179]
  PIN f_d[180]
    DIRECTION INPUT ;
    USE SIGNAL ;
    PORT
      LAYER M5 ;
        RECT 66.8160 189.9960 66.8400 190.0800 ;
    END
  END f_d[180]
  PIN f_d[181]
    DIRECTION INPUT ;
    USE SIGNAL ;
    PORT
      LAYER M5 ;
        RECT 67.1040 189.9960 67.1280 190.0800 ;
    END
  END f_d[181]
  PIN f_d[182]
    DIRECTION INPUT ;
    USE SIGNAL ;
    PORT
      LAYER M5 ;
        RECT 67.3920 189.9960 67.4160 190.0800 ;
    END
  END f_d[182]
  PIN f_d[183]
    DIRECTION INPUT ;
    USE SIGNAL ;
    PORT
      LAYER M5 ;
        RECT 67.7280 189.9960 67.7520 190.0800 ;
    END
  END f_d[183]
  PIN f_d[184]
    DIRECTION INPUT ;
    USE SIGNAL ;
    PORT
      LAYER M5 ;
        RECT 68.0160 189.9960 68.0400 190.0800 ;
    END
  END f_d[184]
  PIN f_d[185]
    DIRECTION INPUT ;
    USE SIGNAL ;
    PORT
      LAYER M5 ;
        RECT 68.3040 189.9960 68.3280 190.0800 ;
    END
  END f_d[185]
  PIN f_d[186]
    DIRECTION INPUT ;
    USE SIGNAL ;
    PORT
      LAYER M5 ;
        RECT 68.5920 189.9960 68.6160 190.0800 ;
    END
  END f_d[186]
  PIN f_d[187]
    DIRECTION INPUT ;
    USE SIGNAL ;
    PORT
      LAYER M5 ;
        RECT 68.9280 189.9960 68.9520 190.0800 ;
    END
  END f_d[187]
  PIN f_d[188]
    DIRECTION INPUT ;
    USE SIGNAL ;
    PORT
      LAYER M5 ;
        RECT 69.2160 189.9960 69.2400 190.0800 ;
    END
  END f_d[188]
  PIN f_d[189]
    DIRECTION INPUT ;
    USE SIGNAL ;
    PORT
      LAYER M5 ;
        RECT 69.5040 189.9960 69.5280 190.0800 ;
    END
  END f_d[189]
  PIN f_d[190]
    DIRECTION INPUT ;
    USE SIGNAL ;
    PORT
      LAYER M5 ;
        RECT 69.7920 189.9960 69.8160 190.0800 ;
    END
  END f_d[190]
  PIN f_d[191]
    DIRECTION INPUT ;
    USE SIGNAL ;
    PORT
      LAYER M5 ;
        RECT 70.1280 189.9960 70.1520 190.0800 ;
    END
  END f_d[191]
  PIN f_d[192]
    DIRECTION INPUT ;
    USE SIGNAL ;
    PORT
      LAYER M5 ;
        RECT 70.4160 189.9960 70.4400 190.0800 ;
    END
  END f_d[192]
  PIN f_d[193]
    DIRECTION INPUT ;
    USE SIGNAL ;
    PORT
      LAYER M5 ;
        RECT 70.7040 189.9960 70.7280 190.0800 ;
    END
  END f_d[193]
  PIN f_d[194]
    DIRECTION INPUT ;
    USE SIGNAL ;
    PORT
      LAYER M5 ;
        RECT 71.0400 189.9960 71.0640 190.0800 ;
    END
  END f_d[194]
  PIN f_d[195]
    DIRECTION INPUT ;
    USE SIGNAL ;
    PORT
      LAYER M5 ;
        RECT 71.3280 189.9960 71.3520 190.0800 ;
    END
  END f_d[195]
  PIN f_d[196]
    DIRECTION INPUT ;
    USE SIGNAL ;
    PORT
      LAYER M5 ;
        RECT 71.6160 189.9960 71.6400 190.0800 ;
    END
  END f_d[196]
  PIN f_d[197]
    DIRECTION INPUT ;
    USE SIGNAL ;
    PORT
      LAYER M5 ;
        RECT 71.9040 189.9960 71.9280 190.0800 ;
    END
  END f_d[197]
  PIN f_d[198]
    DIRECTION INPUT ;
    USE SIGNAL ;
    PORT
      LAYER M5 ;
        RECT 72.2400 189.9960 72.2640 190.0800 ;
    END
  END f_d[198]
  PIN f_d[199]
    DIRECTION INPUT ;
    USE SIGNAL ;
    PORT
      LAYER M5 ;
        RECT 72.5280 189.9960 72.5520 190.0800 ;
    END
  END f_d[199]
  PIN f_d[200]
    DIRECTION INPUT ;
    USE SIGNAL ;
    PORT
      LAYER M5 ;
        RECT 72.8160 189.9960 72.8400 190.0800 ;
    END
  END f_d[200]
  PIN f_d[201]
    DIRECTION INPUT ;
    USE SIGNAL ;
    PORT
      LAYER M5 ;
        RECT 73.1040 189.9960 73.1280 190.0800 ;
    END
  END f_d[201]
  PIN f_d[202]
    DIRECTION INPUT ;
    USE SIGNAL ;
    PORT
      LAYER M5 ;
        RECT 73.4400 189.9960 73.4640 190.0800 ;
    END
  END f_d[202]
  PIN f_d[203]
    DIRECTION INPUT ;
    USE SIGNAL ;
    PORT
      LAYER M5 ;
        RECT 73.7280 189.9960 73.7520 190.0800 ;
    END
  END f_d[203]
  PIN f_d[204]
    DIRECTION INPUT ;
    USE SIGNAL ;
    PORT
      LAYER M5 ;
        RECT 74.0160 189.9960 74.0400 190.0800 ;
    END
  END f_d[204]
  PIN f_d[205]
    DIRECTION INPUT ;
    USE SIGNAL ;
    PORT
      LAYER M5 ;
        RECT 74.3040 189.9960 74.3280 190.0800 ;
    END
  END f_d[205]
  PIN f_d[206]
    DIRECTION INPUT ;
    USE SIGNAL ;
    PORT
      LAYER M5 ;
        RECT 74.6400 189.9960 74.6640 190.0800 ;
    END
  END f_d[206]
  PIN f_d[207]
    DIRECTION INPUT ;
    USE SIGNAL ;
    PORT
      LAYER M5 ;
        RECT 74.9280 189.9960 74.9520 190.0800 ;
    END
  END f_d[207]
  PIN f_d[208]
    DIRECTION INPUT ;
    USE SIGNAL ;
    PORT
      LAYER M5 ;
        RECT 75.2160 189.9960 75.2400 190.0800 ;
    END
  END f_d[208]
  PIN f_d[209]
    DIRECTION INPUT ;
    USE SIGNAL ;
    PORT
      LAYER M5 ;
        RECT 75.5040 189.9960 75.5280 190.0800 ;
    END
  END f_d[209]
  PIN f_d[210]
    DIRECTION INPUT ;
    USE SIGNAL ;
    PORT
      LAYER M5 ;
        RECT 75.8400 189.9960 75.8640 190.0800 ;
    END
  END f_d[210]
  PIN f_d[211]
    DIRECTION INPUT ;
    USE SIGNAL ;
    PORT
      LAYER M5 ;
        RECT 76.1280 189.9960 76.1520 190.0800 ;
    END
  END f_d[211]
  PIN f_d[212]
    DIRECTION INPUT ;
    USE SIGNAL ;
    PORT
      LAYER M5 ;
        RECT 76.4160 189.9960 76.4400 190.0800 ;
    END
  END f_d[212]
  PIN f_d[213]
    DIRECTION INPUT ;
    USE SIGNAL ;
    PORT
      LAYER M5 ;
        RECT 76.7040 189.9960 76.7280 190.0800 ;
    END
  END f_d[213]
  PIN f_d[214]
    DIRECTION INPUT ;
    USE SIGNAL ;
    PORT
      LAYER M5 ;
        RECT 77.0400 189.9960 77.0640 190.0800 ;
    END
  END f_d[214]
  PIN f_d[215]
    DIRECTION INPUT ;
    USE SIGNAL ;
    PORT
      LAYER M5 ;
        RECT 77.3280 189.9960 77.3520 190.0800 ;
    END
  END f_d[215]
  PIN f_d[216]
    DIRECTION INPUT ;
    USE SIGNAL ;
    PORT
      LAYER M5 ;
        RECT 77.6160 189.9960 77.6400 190.0800 ;
    END
  END f_d[216]
  PIN f_d[217]
    DIRECTION INPUT ;
    USE SIGNAL ;
    PORT
      LAYER M5 ;
        RECT 77.9040 189.9960 77.9280 190.0800 ;
    END
  END f_d[217]
  PIN f_d[218]
    DIRECTION INPUT ;
    USE SIGNAL ;
    PORT
      LAYER M5 ;
        RECT 78.2400 189.9960 78.2640 190.0800 ;
    END
  END f_d[218]
  PIN f_d[219]
    DIRECTION INPUT ;
    USE SIGNAL ;
    PORT
      LAYER M5 ;
        RECT 78.5280 189.9960 78.5520 190.0800 ;
    END
  END f_d[219]
  PIN f_d[220]
    DIRECTION INPUT ;
    USE SIGNAL ;
    PORT
      LAYER M5 ;
        RECT 78.8160 189.9960 78.8400 190.0800 ;
    END
  END f_d[220]
  PIN f_d[221]
    DIRECTION INPUT ;
    USE SIGNAL ;
    PORT
      LAYER M5 ;
        RECT 79.1520 189.9960 79.1760 190.0800 ;
    END
  END f_d[221]
  PIN f_d[222]
    DIRECTION INPUT ;
    USE SIGNAL ;
    PORT
      LAYER M5 ;
        RECT 79.4400 189.9960 79.4640 190.0800 ;
    END
  END f_d[222]
  PIN f_d[223]
    DIRECTION INPUT ;
    USE SIGNAL ;
    PORT
      LAYER M5 ;
        RECT 79.7280 189.9960 79.7520 190.0800 ;
    END
  END f_d[223]
  PIN f_d[224]
    DIRECTION INPUT ;
    USE SIGNAL ;
    PORT
      LAYER M5 ;
        RECT 80.0160 189.9960 80.0400 190.0800 ;
    END
  END f_d[224]
  PIN f_d[225]
    DIRECTION INPUT ;
    USE SIGNAL ;
    PORT
      LAYER M5 ;
        RECT 80.3520 189.9960 80.3760 190.0800 ;
    END
  END f_d[225]
  PIN f_d[226]
    DIRECTION INPUT ;
    USE SIGNAL ;
    PORT
      LAYER M5 ;
        RECT 80.6400 189.9960 80.6640 190.0800 ;
    END
  END f_d[226]
  PIN f_d[227]
    DIRECTION INPUT ;
    USE SIGNAL ;
    PORT
      LAYER M5 ;
        RECT 80.9280 189.9960 80.9520 190.0800 ;
    END
  END f_d[227]
  PIN f_d[228]
    DIRECTION INPUT ;
    USE SIGNAL ;
    PORT
      LAYER M5 ;
        RECT 81.2160 189.9960 81.2400 190.0800 ;
    END
  END f_d[228]
  PIN f_d[229]
    DIRECTION INPUT ;
    USE SIGNAL ;
    PORT
      LAYER M5 ;
        RECT 81.5520 189.9960 81.5760 190.0800 ;
    END
  END f_d[229]
  PIN f_d[230]
    DIRECTION INPUT ;
    USE SIGNAL ;
    PORT
      LAYER M5 ;
        RECT 81.8400 189.9960 81.8640 190.0800 ;
    END
  END f_d[230]
  PIN f_d[231]
    DIRECTION INPUT ;
    USE SIGNAL ;
    PORT
      LAYER M5 ;
        RECT 82.1280 189.9960 82.1520 190.0800 ;
    END
  END f_d[231]
  PIN f_d[232]
    DIRECTION INPUT ;
    USE SIGNAL ;
    PORT
      LAYER M5 ;
        RECT 82.4160 189.9960 82.4400 190.0800 ;
    END
  END f_d[232]
  PIN f_d[233]
    DIRECTION INPUT ;
    USE SIGNAL ;
    PORT
      LAYER M5 ;
        RECT 82.7520 189.9960 82.7760 190.0800 ;
    END
  END f_d[233]
  PIN f_d[234]
    DIRECTION INPUT ;
    USE SIGNAL ;
    PORT
      LAYER M5 ;
        RECT 83.0400 189.9960 83.0640 190.0800 ;
    END
  END f_d[234]
  PIN f_d[235]
    DIRECTION INPUT ;
    USE SIGNAL ;
    PORT
      LAYER M5 ;
        RECT 83.3280 189.9960 83.3520 190.0800 ;
    END
  END f_d[235]
  PIN f_d[236]
    DIRECTION INPUT ;
    USE SIGNAL ;
    PORT
      LAYER M5 ;
        RECT 83.6160 189.9960 83.6400 190.0800 ;
    END
  END f_d[236]
  PIN f_d[237]
    DIRECTION INPUT ;
    USE SIGNAL ;
    PORT
      LAYER M5 ;
        RECT 83.9520 189.9960 83.9760 190.0800 ;
    END
  END f_d[237]
  PIN f_d[238]
    DIRECTION INPUT ;
    USE SIGNAL ;
    PORT
      LAYER M5 ;
        RECT 84.2400 189.9960 84.2640 190.0800 ;
    END
  END f_d[238]
  PIN f_d[239]
    DIRECTION INPUT ;
    USE SIGNAL ;
    PORT
      LAYER M5 ;
        RECT 84.5280 189.9960 84.5520 190.0800 ;
    END
  END f_d[239]
  PIN f_d[240]
    DIRECTION INPUT ;
    USE SIGNAL ;
    PORT
      LAYER M5 ;
        RECT 84.8160 189.9960 84.8400 190.0800 ;
    END
  END f_d[240]
  PIN f_d[241]
    DIRECTION INPUT ;
    USE SIGNAL ;
    PORT
      LAYER M5 ;
        RECT 85.1520 189.9960 85.1760 190.0800 ;
    END
  END f_d[241]
  PIN f_d[242]
    DIRECTION INPUT ;
    USE SIGNAL ;
    PORT
      LAYER M5 ;
        RECT 85.4400 189.9960 85.4640 190.0800 ;
    END
  END f_d[242]
  PIN f_d[243]
    DIRECTION INPUT ;
    USE SIGNAL ;
    PORT
      LAYER M5 ;
        RECT 85.7280 189.9960 85.7520 190.0800 ;
    END
  END f_d[243]
  PIN f_d[244]
    DIRECTION INPUT ;
    USE SIGNAL ;
    PORT
      LAYER M5 ;
        RECT 86.0160 189.9960 86.0400 190.0800 ;
    END
  END f_d[244]
  PIN f_d[245]
    DIRECTION INPUT ;
    USE SIGNAL ;
    PORT
      LAYER M5 ;
        RECT 86.3520 189.9960 86.3760 190.0800 ;
    END
  END f_d[245]
  PIN f_d[246]
    DIRECTION INPUT ;
    USE SIGNAL ;
    PORT
      LAYER M5 ;
        RECT 86.6400 189.9960 86.6640 190.0800 ;
    END
  END f_d[246]
  PIN f_d[247]
    DIRECTION INPUT ;
    USE SIGNAL ;
    PORT
      LAYER M5 ;
        RECT 86.9280 189.9960 86.9520 190.0800 ;
    END
  END f_d[247]
  PIN f_d[248]
    DIRECTION INPUT ;
    USE SIGNAL ;
    PORT
      LAYER M5 ;
        RECT 87.2640 189.9960 87.2880 190.0800 ;
    END
  END f_d[248]
  PIN f_d[249]
    DIRECTION INPUT ;
    USE SIGNAL ;
    PORT
      LAYER M5 ;
        RECT 87.5520 189.9960 87.5760 190.0800 ;
    END
  END f_d[249]
  PIN f_d[250]
    DIRECTION INPUT ;
    USE SIGNAL ;
    PORT
      LAYER M5 ;
        RECT 87.8400 189.9960 87.8640 190.0800 ;
    END
  END f_d[250]
  PIN f_d[251]
    DIRECTION INPUT ;
    USE SIGNAL ;
    PORT
      LAYER M5 ;
        RECT 88.1280 189.9960 88.1520 190.0800 ;
    END
  END f_d[251]
  PIN f_d[252]
    DIRECTION INPUT ;
    USE SIGNAL ;
    PORT
      LAYER M5 ;
        RECT 88.4640 189.9960 88.4880 190.0800 ;
    END
  END f_d[252]
  PIN f_d[253]
    DIRECTION INPUT ;
    USE SIGNAL ;
    PORT
      LAYER M5 ;
        RECT 88.7520 189.9960 88.7760 190.0800 ;
    END
  END f_d[253]
  PIN f_d[254]
    DIRECTION INPUT ;
    USE SIGNAL ;
    PORT
      LAYER M5 ;
        RECT 89.0400 189.9960 89.0640 190.0800 ;
    END
  END f_d[254]
  PIN f_d[255]
    DIRECTION INPUT ;
    USE SIGNAL ;
    PORT
      LAYER M5 ;
        RECT 89.3280 189.9960 89.3520 190.0800 ;
    END
  END f_d[255]
  PIN f_d[256]
    DIRECTION INPUT ;
    USE SIGNAL ;
    PORT
      LAYER M5 ;
        RECT 89.6640 189.9960 89.6880 190.0800 ;
    END
  END f_d[256]
  PIN f_d[257]
    DIRECTION INPUT ;
    USE SIGNAL ;
    PORT
      LAYER M5 ;
        RECT 89.9520 189.9960 89.9760 190.0800 ;
    END
  END f_d[257]
  PIN f_d[258]
    DIRECTION INPUT ;
    USE SIGNAL ;
    PORT
      LAYER M5 ;
        RECT 90.2400 189.9960 90.2640 190.0800 ;
    END
  END f_d[258]
  PIN f_d[259]
    DIRECTION INPUT ;
    USE SIGNAL ;
    PORT
      LAYER M5 ;
        RECT 90.5280 189.9960 90.5520 190.0800 ;
    END
  END f_d[259]
  PIN f_d[260]
    DIRECTION INPUT ;
    USE SIGNAL ;
    PORT
      LAYER M5 ;
        RECT 90.8640 189.9960 90.8880 190.0800 ;
    END
  END f_d[260]
  PIN f_d[261]
    DIRECTION INPUT ;
    USE SIGNAL ;
    PORT
      LAYER M5 ;
        RECT 91.1520 189.9960 91.1760 190.0800 ;
    END
  END f_d[261]
  PIN f_d[262]
    DIRECTION INPUT ;
    USE SIGNAL ;
    PORT
      LAYER M5 ;
        RECT 91.4400 189.9960 91.4640 190.0800 ;
    END
  END f_d[262]
  PIN f_d[263]
    DIRECTION INPUT ;
    USE SIGNAL ;
    PORT
      LAYER M5 ;
        RECT 91.7280 189.9960 91.7520 190.0800 ;
    END
  END f_d[263]
  PIN f_d[264]
    DIRECTION INPUT ;
    USE SIGNAL ;
    PORT
      LAYER M5 ;
        RECT 92.0640 189.9960 92.0880 190.0800 ;
    END
  END f_d[264]
  PIN f_d[265]
    DIRECTION INPUT ;
    USE SIGNAL ;
    PORT
      LAYER M5 ;
        RECT 92.3520 189.9960 92.3760 190.0800 ;
    END
  END f_d[265]
  PIN f_d[266]
    DIRECTION INPUT ;
    USE SIGNAL ;
    PORT
      LAYER M5 ;
        RECT 92.6400 189.9960 92.6640 190.0800 ;
    END
  END f_d[266]
  PIN f_d[267]
    DIRECTION INPUT ;
    USE SIGNAL ;
    PORT
      LAYER M5 ;
        RECT 92.9280 189.9960 92.9520 190.0800 ;
    END
  END f_d[267]
  PIN f_d[268]
    DIRECTION INPUT ;
    USE SIGNAL ;
    PORT
      LAYER M5 ;
        RECT 93.2640 189.9960 93.2880 190.0800 ;
    END
  END f_d[268]
  PIN f_d[269]
    DIRECTION INPUT ;
    USE SIGNAL ;
    PORT
      LAYER M5 ;
        RECT 93.5520 189.9960 93.5760 190.0800 ;
    END
  END f_d[269]
  PIN f_d[270]
    DIRECTION INPUT ;
    USE SIGNAL ;
    PORT
      LAYER M5 ;
        RECT 93.8400 189.9960 93.8640 190.0800 ;
    END
  END f_d[270]
  PIN f_d[271]
    DIRECTION INPUT ;
    USE SIGNAL ;
    PORT
      LAYER M5 ;
        RECT 94.1280 189.9960 94.1520 190.0800 ;
    END
  END f_d[271]
  PIN f_d[272]
    DIRECTION INPUT ;
    USE SIGNAL ;
    PORT
      LAYER M5 ;
        RECT 94.4640 189.9960 94.4880 190.0800 ;
    END
  END f_d[272]
  PIN f_d[273]
    DIRECTION INPUT ;
    USE SIGNAL ;
    PORT
      LAYER M5 ;
        RECT 94.7520 189.9960 94.7760 190.0800 ;
    END
  END f_d[273]
  PIN f_d[274]
    DIRECTION INPUT ;
    USE SIGNAL ;
    PORT
      LAYER M5 ;
        RECT 95.0400 189.9960 95.0640 190.0800 ;
    END
  END f_d[274]
  PIN f_d[275]
    DIRECTION INPUT ;
    USE SIGNAL ;
    PORT
      LAYER M5 ;
        RECT 95.3760 189.9960 95.4000 190.0800 ;
    END
  END f_d[275]
  PIN f_d[276]
    DIRECTION INPUT ;
    USE SIGNAL ;
    PORT
      LAYER M5 ;
        RECT 95.6640 189.9960 95.6880 190.0800 ;
    END
  END f_d[276]
  PIN f_d[277]
    DIRECTION INPUT ;
    USE SIGNAL ;
    PORT
      LAYER M5 ;
        RECT 95.9520 189.9960 95.9760 190.0800 ;
    END
  END f_d[277]
  PIN f_d[278]
    DIRECTION INPUT ;
    USE SIGNAL ;
    PORT
      LAYER M5 ;
        RECT 96.2400 189.9960 96.2640 190.0800 ;
    END
  END f_d[278]
  PIN f_d[279]
    DIRECTION INPUT ;
    USE SIGNAL ;
    PORT
      LAYER M5 ;
        RECT 96.5760 189.9960 96.6000 190.0800 ;
    END
  END f_d[279]
  PIN f_d[280]
    DIRECTION INPUT ;
    USE SIGNAL ;
    PORT
      LAYER M5 ;
        RECT 96.8640 189.9960 96.8880 190.0800 ;
    END
  END f_d[280]
  PIN f_d[281]
    DIRECTION INPUT ;
    USE SIGNAL ;
    PORT
      LAYER M5 ;
        RECT 97.1520 189.9960 97.1760 190.0800 ;
    END
  END f_d[281]
  PIN f_d[282]
    DIRECTION INPUT ;
    USE SIGNAL ;
    PORT
      LAYER M5 ;
        RECT 97.4400 189.9960 97.4640 190.0800 ;
    END
  END f_d[282]
  PIN f_d[283]
    DIRECTION INPUT ;
    USE SIGNAL ;
    PORT
      LAYER M5 ;
        RECT 97.7760 189.9960 97.8000 190.0800 ;
    END
  END f_d[283]
  PIN f_d[284]
    DIRECTION INPUT ;
    USE SIGNAL ;
    PORT
      LAYER M5 ;
        RECT 98.0640 189.9960 98.0880 190.0800 ;
    END
  END f_d[284]
  PIN f_d[285]
    DIRECTION INPUT ;
    USE SIGNAL ;
    PORT
      LAYER M5 ;
        RECT 98.3520 189.9960 98.3760 190.0800 ;
    END
  END f_d[285]
  PIN f_d[286]
    DIRECTION INPUT ;
    USE SIGNAL ;
    PORT
      LAYER M5 ;
        RECT 98.6400 189.9960 98.6640 190.0800 ;
    END
  END f_d[286]
  PIN f_d[287]
    DIRECTION INPUT ;
    USE SIGNAL ;
    PORT
      LAYER M5 ;
        RECT 98.9760 189.9960 99.0000 190.0800 ;
    END
  END f_d[287]
  PIN f_d[288]
    DIRECTION INPUT ;
    USE SIGNAL ;
    PORT
      LAYER M5 ;
        RECT 99.2640 189.9960 99.2880 190.0800 ;
    END
  END f_d[288]
  PIN f_d[289]
    DIRECTION INPUT ;
    USE SIGNAL ;
    PORT
      LAYER M5 ;
        RECT 99.5520 189.9960 99.5760 190.0800 ;
    END
  END f_d[289]
  PIN f_d[290]
    DIRECTION INPUT ;
    USE SIGNAL ;
    PORT
      LAYER M5 ;
        RECT 99.8400 189.9960 99.8640 190.0800 ;
    END
  END f_d[290]
  PIN f_d[291]
    DIRECTION INPUT ;
    USE SIGNAL ;
    PORT
      LAYER M5 ;
        RECT 100.1760 189.9960 100.2000 190.0800 ;
    END
  END f_d[291]
  PIN f_d[292]
    DIRECTION INPUT ;
    USE SIGNAL ;
    PORT
      LAYER M5 ;
        RECT 100.4640 189.9960 100.4880 190.0800 ;
    END
  END f_d[292]
  PIN f_d[293]
    DIRECTION INPUT ;
    USE SIGNAL ;
    PORT
      LAYER M5 ;
        RECT 100.7520 189.9960 100.7760 190.0800 ;
    END
  END f_d[293]
  PIN f_d[294]
    DIRECTION INPUT ;
    USE SIGNAL ;
    PORT
      LAYER M5 ;
        RECT 101.0400 189.9960 101.0640 190.0800 ;
    END
  END f_d[294]
  PIN f_d[295]
    DIRECTION INPUT ;
    USE SIGNAL ;
    PORT
      LAYER M5 ;
        RECT 101.3760 189.9960 101.4000 190.0800 ;
    END
  END f_d[295]
  PIN f_d[296]
    DIRECTION INPUT ;
    USE SIGNAL ;
    PORT
      LAYER M5 ;
        RECT 101.6640 189.9960 101.6880 190.0800 ;
    END
  END f_d[296]
  PIN f_d[297]
    DIRECTION INPUT ;
    USE SIGNAL ;
    PORT
      LAYER M5 ;
        RECT 101.9520 189.9960 101.9760 190.0800 ;
    END
  END f_d[297]
  PIN f_d[298]
    DIRECTION INPUT ;
    USE SIGNAL ;
    PORT
      LAYER M5 ;
        RECT 102.2400 189.9960 102.2640 190.0800 ;
    END
  END f_d[298]
  PIN f_d[299]
    DIRECTION INPUT ;
    USE SIGNAL ;
    PORT
      LAYER M5 ;
        RECT 102.5760 189.9960 102.6000 190.0800 ;
    END
  END f_d[299]
  PIN f_d[300]
    DIRECTION INPUT ;
    USE SIGNAL ;
    PORT
      LAYER M5 ;
        RECT 102.8640 189.9960 102.8880 190.0800 ;
    END
  END f_d[300]
  PIN f_d[301]
    DIRECTION INPUT ;
    USE SIGNAL ;
    PORT
      LAYER M5 ;
        RECT 103.1520 189.9960 103.1760 190.0800 ;
    END
  END f_d[301]
  PIN f_d[302]
    DIRECTION INPUT ;
    USE SIGNAL ;
    PORT
      LAYER M5 ;
        RECT 103.4880 189.9960 103.5120 190.0800 ;
    END
  END f_d[302]
  PIN f_d[303]
    DIRECTION INPUT ;
    USE SIGNAL ;
    PORT
      LAYER M5 ;
        RECT 103.7760 189.9960 103.8000 190.0800 ;
    END
  END f_d[303]
  PIN f_d[304]
    DIRECTION INPUT ;
    USE SIGNAL ;
    PORT
      LAYER M5 ;
        RECT 104.0640 189.9960 104.0880 190.0800 ;
    END
  END f_d[304]
  PIN f_d[305]
    DIRECTION INPUT ;
    USE SIGNAL ;
    PORT
      LAYER M5 ;
        RECT 104.3520 189.9960 104.3760 190.0800 ;
    END
  END f_d[305]
  PIN f_d[306]
    DIRECTION INPUT ;
    USE SIGNAL ;
    PORT
      LAYER M5 ;
        RECT 104.6880 189.9960 104.7120 190.0800 ;
    END
  END f_d[306]
  PIN f_d[307]
    DIRECTION INPUT ;
    USE SIGNAL ;
    PORT
      LAYER M5 ;
        RECT 104.9760 189.9960 105.0000 190.0800 ;
    END
  END f_d[307]
  PIN f_d[308]
    DIRECTION INPUT ;
    USE SIGNAL ;
    PORT
      LAYER M5 ;
        RECT 105.2640 189.9960 105.2880 190.0800 ;
    END
  END f_d[308]
  PIN f_d[309]
    DIRECTION INPUT ;
    USE SIGNAL ;
    PORT
      LAYER M5 ;
        RECT 105.5520 189.9960 105.5760 190.0800 ;
    END
  END f_d[309]
  PIN f_d[310]
    DIRECTION INPUT ;
    USE SIGNAL ;
    PORT
      LAYER M5 ;
        RECT 105.8880 189.9960 105.9120 190.0800 ;
    END
  END f_d[310]
  PIN f_d[311]
    DIRECTION INPUT ;
    USE SIGNAL ;
    PORT
      LAYER M5 ;
        RECT 106.1760 189.9960 106.2000 190.0800 ;
    END
  END f_d[311]
  PIN f_d[312]
    DIRECTION INPUT ;
    USE SIGNAL ;
    PORT
      LAYER M5 ;
        RECT 106.4640 189.9960 106.4880 190.0800 ;
    END
  END f_d[312]
  PIN f_d[313]
    DIRECTION INPUT ;
    USE SIGNAL ;
    PORT
      LAYER M5 ;
        RECT 106.7520 189.9960 106.7760 190.0800 ;
    END
  END f_d[313]
  PIN f_d[314]
    DIRECTION INPUT ;
    USE SIGNAL ;
    PORT
      LAYER M5 ;
        RECT 107.0880 189.9960 107.1120 190.0800 ;
    END
  END f_d[314]
  PIN f_d[315]
    DIRECTION INPUT ;
    USE SIGNAL ;
    PORT
      LAYER M5 ;
        RECT 107.3760 189.9960 107.4000 190.0800 ;
    END
  END f_d[315]
  PIN f_d[316]
    DIRECTION INPUT ;
    USE SIGNAL ;
    PORT
      LAYER M5 ;
        RECT 107.6640 189.9960 107.6880 190.0800 ;
    END
  END f_d[316]
  PIN f_d[317]
    DIRECTION INPUT ;
    USE SIGNAL ;
    PORT
      LAYER M5 ;
        RECT 107.9520 189.9960 107.9760 190.0800 ;
    END
  END f_d[317]
  PIN f_d[318]
    DIRECTION INPUT ;
    USE SIGNAL ;
    PORT
      LAYER M5 ;
        RECT 108.2880 189.9960 108.3120 190.0800 ;
    END
  END f_d[318]
  PIN f_d[319]
    DIRECTION INPUT ;
    USE SIGNAL ;
    PORT
      LAYER M5 ;
        RECT 108.5760 189.9960 108.6000 190.0800 ;
    END
  END f_d[319]
  PIN f_d[320]
    DIRECTION INPUT ;
    USE SIGNAL ;
    PORT
      LAYER M5 ;
        RECT 108.8640 189.9960 108.8880 190.0800 ;
    END
  END f_d[320]
  PIN f_d[321]
    DIRECTION INPUT ;
    USE SIGNAL ;
    PORT
      LAYER M5 ;
        RECT 109.1520 189.9960 109.1760 190.0800 ;
    END
  END f_d[321]
  PIN f_d[322]
    DIRECTION INPUT ;
    USE SIGNAL ;
    PORT
      LAYER M5 ;
        RECT 109.4880 189.9960 109.5120 190.0800 ;
    END
  END f_d[322]
  PIN f_d[323]
    DIRECTION INPUT ;
    USE SIGNAL ;
    PORT
      LAYER M5 ;
        RECT 109.7760 189.9960 109.8000 190.0800 ;
    END
  END f_d[323]
  PIN f_d[324]
    DIRECTION INPUT ;
    USE SIGNAL ;
    PORT
      LAYER M5 ;
        RECT 110.0640 189.9960 110.0880 190.0800 ;
    END
  END f_d[324]
  PIN f_d[325]
    DIRECTION INPUT ;
    USE SIGNAL ;
    PORT
      LAYER M5 ;
        RECT 110.3520 189.9960 110.3760 190.0800 ;
    END
  END f_d[325]
  PIN f_d[326]
    DIRECTION INPUT ;
    USE SIGNAL ;
    PORT
      LAYER M5 ;
        RECT 110.6880 189.9960 110.7120 190.0800 ;
    END
  END f_d[326]
  PIN f_d[327]
    DIRECTION INPUT ;
    USE SIGNAL ;
    PORT
      LAYER M5 ;
        RECT 110.9760 189.9960 111.0000 190.0800 ;
    END
  END f_d[327]
  PIN f_d[328]
    DIRECTION INPUT ;
    USE SIGNAL ;
    PORT
      LAYER M5 ;
        RECT 111.2640 189.9960 111.2880 190.0800 ;
    END
  END f_d[328]
  PIN f_d[329]
    DIRECTION INPUT ;
    USE SIGNAL ;
    PORT
      LAYER M5 ;
        RECT 111.6000 189.9960 111.6240 190.0800 ;
    END
  END f_d[329]
  PIN f_d[330]
    DIRECTION INPUT ;
    USE SIGNAL ;
    PORT
      LAYER M5 ;
        RECT 111.8880 189.9960 111.9120 190.0800 ;
    END
  END f_d[330]
  PIN f_d[331]
    DIRECTION INPUT ;
    USE SIGNAL ;
    PORT
      LAYER M5 ;
        RECT 112.1760 189.9960 112.2000 190.0800 ;
    END
  END f_d[331]
  PIN f_d[332]
    DIRECTION INPUT ;
    USE SIGNAL ;
    PORT
      LAYER M5 ;
        RECT 112.4640 189.9960 112.4880 190.0800 ;
    END
  END f_d[332]
  PIN f_d[333]
    DIRECTION INPUT ;
    USE SIGNAL ;
    PORT
      LAYER M5 ;
        RECT 112.8000 189.9960 112.8240 190.0800 ;
    END
  END f_d[333]
  PIN f_d[334]
    DIRECTION INPUT ;
    USE SIGNAL ;
    PORT
      LAYER M5 ;
        RECT 113.0880 189.9960 113.1120 190.0800 ;
    END
  END f_d[334]
  PIN f_d[335]
    DIRECTION INPUT ;
    USE SIGNAL ;
    PORT
      LAYER M5 ;
        RECT 113.3760 189.9960 113.4000 190.0800 ;
    END
  END f_d[335]
  PIN f_d[336]
    DIRECTION INPUT ;
    USE SIGNAL ;
    PORT
      LAYER M5 ;
        RECT 113.6640 189.9960 113.6880 190.0800 ;
    END
  END f_d[336]
  PIN f_d[337]
    DIRECTION INPUT ;
    USE SIGNAL ;
    PORT
      LAYER M5 ;
        RECT 114.0000 189.9960 114.0240 190.0800 ;
    END
  END f_d[337]
  PIN f_d[338]
    DIRECTION INPUT ;
    USE SIGNAL ;
    PORT
      LAYER M5 ;
        RECT 114.2880 189.9960 114.3120 190.0800 ;
    END
  END f_d[338]
  PIN f_d[339]
    DIRECTION INPUT ;
    USE SIGNAL ;
    PORT
      LAYER M5 ;
        RECT 114.5760 189.9960 114.6000 190.0800 ;
    END
  END f_d[339]
  PIN f_d[340]
    DIRECTION INPUT ;
    USE SIGNAL ;
    PORT
      LAYER M5 ;
        RECT 114.8640 189.9960 114.8880 190.0800 ;
    END
  END f_d[340]
  PIN f_d[341]
    DIRECTION INPUT ;
    USE SIGNAL ;
    PORT
      LAYER M5 ;
        RECT 115.2000 189.9960 115.2240 190.0800 ;
    END
  END f_d[341]
  PIN f_d[342]
    DIRECTION INPUT ;
    USE SIGNAL ;
    PORT
      LAYER M5 ;
        RECT 115.4880 189.9960 115.5120 190.0800 ;
    END
  END f_d[342]
  PIN f_d[343]
    DIRECTION INPUT ;
    USE SIGNAL ;
    PORT
      LAYER M5 ;
        RECT 115.7760 189.9960 115.8000 190.0800 ;
    END
  END f_d[343]
  PIN f_d[344]
    DIRECTION INPUT ;
    USE SIGNAL ;
    PORT
      LAYER M5 ;
        RECT 116.0640 189.9960 116.0880 190.0800 ;
    END
  END f_d[344]
  PIN f_d[345]
    DIRECTION INPUT ;
    USE SIGNAL ;
    PORT
      LAYER M5 ;
        RECT 116.4000 189.9960 116.4240 190.0800 ;
    END
  END f_d[345]
  PIN f_d[346]
    DIRECTION INPUT ;
    USE SIGNAL ;
    PORT
      LAYER M5 ;
        RECT 116.6880 189.9960 116.7120 190.0800 ;
    END
  END f_d[346]
  PIN f_d[347]
    DIRECTION INPUT ;
    USE SIGNAL ;
    PORT
      LAYER M5 ;
        RECT 116.9760 189.9960 117.0000 190.0800 ;
    END
  END f_d[347]
  PIN f_d[348]
    DIRECTION INPUT ;
    USE SIGNAL ;
    PORT
      LAYER M5 ;
        RECT 117.2640 189.9960 117.2880 190.0800 ;
    END
  END f_d[348]
  PIN f_d[349]
    DIRECTION INPUT ;
    USE SIGNAL ;
    PORT
      LAYER M5 ;
        RECT 117.6000 189.9960 117.6240 190.0800 ;
    END
  END f_d[349]
  PIN f_d[350]
    DIRECTION INPUT ;
    USE SIGNAL ;
    PORT
      LAYER M5 ;
        RECT 117.8880 189.9960 117.9120 190.0800 ;
    END
  END f_d[350]
  PIN f_d[351]
    DIRECTION INPUT ;
    USE SIGNAL ;
    PORT
      LAYER M5 ;
        RECT 118.1760 189.9960 118.2000 190.0800 ;
    END
  END f_d[351]
  PIN f_d[352]
    DIRECTION INPUT ;
    USE SIGNAL ;
    PORT
      LAYER M5 ;
        RECT 118.4640 189.9960 118.4880 190.0800 ;
    END
  END f_d[352]
  PIN f_d[353]
    DIRECTION INPUT ;
    USE SIGNAL ;
    PORT
      LAYER M5 ;
        RECT 118.8000 189.9960 118.8240 190.0800 ;
    END
  END f_d[353]
  PIN f_d[354]
    DIRECTION INPUT ;
    USE SIGNAL ;
    PORT
      LAYER M5 ;
        RECT 119.0880 189.9960 119.1120 190.0800 ;
    END
  END f_d[354]
  PIN f_d[355]
    DIRECTION INPUT ;
    USE SIGNAL ;
    PORT
      LAYER M5 ;
        RECT 119.3760 189.9960 119.4000 190.0800 ;
    END
  END f_d[355]
  PIN f_d[356]
    DIRECTION INPUT ;
    USE SIGNAL ;
    PORT
      LAYER M5 ;
        RECT 119.7120 189.9960 119.7360 190.0800 ;
    END
  END f_d[356]
  PIN f_d[357]
    DIRECTION INPUT ;
    USE SIGNAL ;
    PORT
      LAYER M5 ;
        RECT 120.0000 189.9960 120.0240 190.0800 ;
    END
  END f_d[357]
  PIN f_d[358]
    DIRECTION INPUT ;
    USE SIGNAL ;
    PORT
      LAYER M5 ;
        RECT 120.2880 189.9960 120.3120 190.0800 ;
    END
  END f_d[358]
  PIN f_d[359]
    DIRECTION INPUT ;
    USE SIGNAL ;
    PORT
      LAYER M5 ;
        RECT 120.5760 189.9960 120.6000 190.0800 ;
    END
  END f_d[359]
  PIN f_d[360]
    DIRECTION INPUT ;
    USE SIGNAL ;
    PORT
      LAYER M5 ;
        RECT 120.9120 189.9960 120.9360 190.0800 ;
    END
  END f_d[360]
  PIN f_d[361]
    DIRECTION INPUT ;
    USE SIGNAL ;
    PORT
      LAYER M5 ;
        RECT 121.2000 189.9960 121.2240 190.0800 ;
    END
  END f_d[361]
  PIN f_d[362]
    DIRECTION INPUT ;
    USE SIGNAL ;
    PORT
      LAYER M5 ;
        RECT 121.4880 189.9960 121.5120 190.0800 ;
    END
  END f_d[362]
  PIN f_d[363]
    DIRECTION INPUT ;
    USE SIGNAL ;
    PORT
      LAYER M5 ;
        RECT 121.7760 189.9960 121.8000 190.0800 ;
    END
  END f_d[363]
  PIN f_d[364]
    DIRECTION INPUT ;
    USE SIGNAL ;
    PORT
      LAYER M5 ;
        RECT 122.1120 189.9960 122.1360 190.0800 ;
    END
  END f_d[364]
  PIN f_d[365]
    DIRECTION INPUT ;
    USE SIGNAL ;
    PORT
      LAYER M5 ;
        RECT 122.4000 189.9960 122.4240 190.0800 ;
    END
  END f_d[365]
  PIN f_d[366]
    DIRECTION INPUT ;
    USE SIGNAL ;
    PORT
      LAYER M5 ;
        RECT 122.6880 189.9960 122.7120 190.0800 ;
    END
  END f_d[366]
  PIN f_d[367]
    DIRECTION INPUT ;
    USE SIGNAL ;
    PORT
      LAYER M5 ;
        RECT 122.9760 189.9960 123.0000 190.0800 ;
    END
  END f_d[367]
  PIN f_d[368]
    DIRECTION INPUT ;
    USE SIGNAL ;
    PORT
      LAYER M5 ;
        RECT 123.3120 189.9960 123.3360 190.0800 ;
    END
  END f_d[368]
  PIN f_d[369]
    DIRECTION INPUT ;
    USE SIGNAL ;
    PORT
      LAYER M5 ;
        RECT 123.6000 189.9960 123.6240 190.0800 ;
    END
  END f_d[369]
  PIN f_d[370]
    DIRECTION INPUT ;
    USE SIGNAL ;
    PORT
      LAYER M5 ;
        RECT 123.8880 189.9960 123.9120 190.0800 ;
    END
  END f_d[370]
  PIN f_d[371]
    DIRECTION INPUT ;
    USE SIGNAL ;
    PORT
      LAYER M5 ;
        RECT 124.1760 189.9960 124.2000 190.0800 ;
    END
  END f_d[371]
  PIN f_d[372]
    DIRECTION INPUT ;
    USE SIGNAL ;
    PORT
      LAYER M5 ;
        RECT 124.5120 189.9960 124.5360 190.0800 ;
    END
  END f_d[372]
  PIN f_d[373]
    DIRECTION INPUT ;
    USE SIGNAL ;
    PORT
      LAYER M5 ;
        RECT 124.8000 189.9960 124.8240 190.0800 ;
    END
  END f_d[373]
  PIN f_d[374]
    DIRECTION INPUT ;
    USE SIGNAL ;
    PORT
      LAYER M5 ;
        RECT 125.0880 189.9960 125.1120 190.0800 ;
    END
  END f_d[374]
  PIN f_d[375]
    DIRECTION INPUT ;
    USE SIGNAL ;
    PORT
      LAYER M5 ;
        RECT 125.3760 189.9960 125.4000 190.0800 ;
    END
  END f_d[375]
  PIN f_d[376]
    DIRECTION INPUT ;
    USE SIGNAL ;
    PORT
      LAYER M5 ;
        RECT 125.7120 189.9960 125.7360 190.0800 ;
    END
  END f_d[376]
  PIN f_d[377]
    DIRECTION INPUT ;
    USE SIGNAL ;
    PORT
      LAYER M5 ;
        RECT 126.0000 189.9960 126.0240 190.0800 ;
    END
  END f_d[377]
  PIN f_d[378]
    DIRECTION INPUT ;
    USE SIGNAL ;
    PORT
      LAYER M5 ;
        RECT 126.2880 189.9960 126.3120 190.0800 ;
    END
  END f_d[378]
  PIN f_d[379]
    DIRECTION INPUT ;
    USE SIGNAL ;
    PORT
      LAYER M5 ;
        RECT 126.5760 189.9960 126.6000 190.0800 ;
    END
  END f_d[379]
  PIN f_d[380]
    DIRECTION INPUT ;
    USE SIGNAL ;
    PORT
      LAYER M5 ;
        RECT 126.9120 189.9960 126.9360 190.0800 ;
    END
  END f_d[380]
  PIN f_d[381]
    DIRECTION INPUT ;
    USE SIGNAL ;
    PORT
      LAYER M5 ;
        RECT 127.2000 189.9960 127.2240 190.0800 ;
    END
  END f_d[381]
  PIN f_d[382]
    DIRECTION INPUT ;
    USE SIGNAL ;
    PORT
      LAYER M5 ;
        RECT 127.4880 189.9960 127.5120 190.0800 ;
    END
  END f_d[382]
  PIN f_d[383]
    DIRECTION INPUT ;
    USE SIGNAL ;
    PORT
      LAYER M5 ;
        RECT 127.8240 189.9960 127.8480 190.0800 ;
    END
  END f_d[383]
  PIN f_d[384]
    DIRECTION INPUT ;
    USE SIGNAL ;
    PORT
      LAYER M5 ;
        RECT 128.1120 189.9960 128.1360 190.0800 ;
    END
  END f_d[384]
  PIN f_d[385]
    DIRECTION INPUT ;
    USE SIGNAL ;
    PORT
      LAYER M5 ;
        RECT 128.4000 189.9960 128.4240 190.0800 ;
    END
  END f_d[385]
  PIN f_d[386]
    DIRECTION INPUT ;
    USE SIGNAL ;
    PORT
      LAYER M5 ;
        RECT 128.6880 189.9960 128.7120 190.0800 ;
    END
  END f_d[386]
  PIN f_d[387]
    DIRECTION INPUT ;
    USE SIGNAL ;
    PORT
      LAYER M5 ;
        RECT 129.0240 189.9960 129.0480 190.0800 ;
    END
  END f_d[387]
  PIN f_d[388]
    DIRECTION INPUT ;
    USE SIGNAL ;
    PORT
      LAYER M5 ;
        RECT 129.3120 189.9960 129.3360 190.0800 ;
    END
  END f_d[388]
  PIN f_d[389]
    DIRECTION INPUT ;
    USE SIGNAL ;
    PORT
      LAYER M5 ;
        RECT 129.6000 189.9960 129.6240 190.0800 ;
    END
  END f_d[389]
  PIN f_d[390]
    DIRECTION INPUT ;
    USE SIGNAL ;
    PORT
      LAYER M5 ;
        RECT 129.8880 189.9960 129.9120 190.0800 ;
    END
  END f_d[390]
  PIN f_d[391]
    DIRECTION INPUT ;
    USE SIGNAL ;
    PORT
      LAYER M5 ;
        RECT 130.2240 189.9960 130.2480 190.0800 ;
    END
  END f_d[391]
  PIN f_d[392]
    DIRECTION INPUT ;
    USE SIGNAL ;
    PORT
      LAYER M5 ;
        RECT 130.5120 189.9960 130.5360 190.0800 ;
    END
  END f_d[392]
  PIN f_d[393]
    DIRECTION INPUT ;
    USE SIGNAL ;
    PORT
      LAYER M5 ;
        RECT 130.8000 189.9960 130.8240 190.0800 ;
    END
  END f_d[393]
  PIN f_d[394]
    DIRECTION INPUT ;
    USE SIGNAL ;
    PORT
      LAYER M5 ;
        RECT 131.0880 189.9960 131.1120 190.0800 ;
    END
  END f_d[394]
  PIN f_d[395]
    DIRECTION INPUT ;
    USE SIGNAL ;
    PORT
      LAYER M5 ;
        RECT 131.4240 189.9960 131.4480 190.0800 ;
    END
  END f_d[395]
  PIN f_d[396]
    DIRECTION INPUT ;
    USE SIGNAL ;
    PORT
      LAYER M5 ;
        RECT 131.7120 189.9960 131.7360 190.0800 ;
    END
  END f_d[396]
  PIN f_d[397]
    DIRECTION INPUT ;
    USE SIGNAL ;
    PORT
      LAYER M5 ;
        RECT 132.0000 189.9960 132.0240 190.0800 ;
    END
  END f_d[397]
  PIN f_d[398]
    DIRECTION INPUT ;
    USE SIGNAL ;
    PORT
      LAYER M5 ;
        RECT 132.2880 189.9960 132.3120 190.0800 ;
    END
  END f_d[398]
  PIN f_d[399]
    DIRECTION INPUT ;
    USE SIGNAL ;
    PORT
      LAYER M5 ;
        RECT 132.6240 189.9960 132.6480 190.0800 ;
    END
  END f_d[399]
  PIN f_d[400]
    DIRECTION INPUT ;
    USE SIGNAL ;
    PORT
      LAYER M5 ;
        RECT 132.9120 189.9960 132.9360 190.0800 ;
    END
  END f_d[400]
  PIN f_d[401]
    DIRECTION INPUT ;
    USE SIGNAL ;
    PORT
      LAYER M5 ;
        RECT 133.2000 189.9960 133.2240 190.0800 ;
    END
  END f_d[401]
  PIN f_d[402]
    DIRECTION INPUT ;
    USE SIGNAL ;
    PORT
      LAYER M5 ;
        RECT 133.4880 189.9960 133.5120 190.0800 ;
    END
  END f_d[402]
  PIN f_d[403]
    DIRECTION INPUT ;
    USE SIGNAL ;
    PORT
      LAYER M5 ;
        RECT 133.8240 189.9960 133.8480 190.0800 ;
    END
  END f_d[403]
  PIN f_d[404]
    DIRECTION INPUT ;
    USE SIGNAL ;
    PORT
      LAYER M5 ;
        RECT 134.1120 189.9960 134.1360 190.0800 ;
    END
  END f_d[404]
  PIN f_d[405]
    DIRECTION INPUT ;
    USE SIGNAL ;
    PORT
      LAYER M5 ;
        RECT 134.4000 189.9960 134.4240 190.0800 ;
    END
  END f_d[405]
  PIN f_d[406]
    DIRECTION INPUT ;
    USE SIGNAL ;
    PORT
      LAYER M5 ;
        RECT 134.6880 189.9960 134.7120 190.0800 ;
    END
  END f_d[406]
  PIN f_d[407]
    DIRECTION INPUT ;
    USE SIGNAL ;
    PORT
      LAYER M5 ;
        RECT 135.0240 189.9960 135.0480 190.0800 ;
    END
  END f_d[407]
  PIN f_d[408]
    DIRECTION INPUT ;
    USE SIGNAL ;
    PORT
      LAYER M5 ;
        RECT 135.3120 189.9960 135.3360 190.0800 ;
    END
  END f_d[408]
  PIN f_d[409]
    DIRECTION INPUT ;
    USE SIGNAL ;
    PORT
      LAYER M5 ;
        RECT 135.6000 189.9960 135.6240 190.0800 ;
    END
  END f_d[409]
  PIN f_d[410]
    DIRECTION INPUT ;
    USE SIGNAL ;
    PORT
      LAYER M5 ;
        RECT 135.8880 189.9960 135.9120 190.0800 ;
    END
  END f_d[410]
  PIN f_d[411]
    DIRECTION INPUT ;
    USE SIGNAL ;
    PORT
      LAYER M5 ;
        RECT 136.2240 189.9960 136.2480 190.0800 ;
    END
  END f_d[411]
  PIN f_d[412]
    DIRECTION INPUT ;
    USE SIGNAL ;
    PORT
      LAYER M5 ;
        RECT 136.5120 189.9960 136.5360 190.0800 ;
    END
  END f_d[412]
  PIN f_d[413]
    DIRECTION INPUT ;
    USE SIGNAL ;
    PORT
      LAYER M5 ;
        RECT 136.8000 189.9960 136.8240 190.0800 ;
    END
  END f_d[413]
  PIN f_d[414]
    DIRECTION INPUT ;
    USE SIGNAL ;
    PORT
      LAYER M5 ;
        RECT 137.1360 189.9960 137.1600 190.0800 ;
    END
  END f_d[414]
  PIN f_d[415]
    DIRECTION INPUT ;
    USE SIGNAL ;
    PORT
      LAYER M5 ;
        RECT 137.4240 189.9960 137.4480 190.0800 ;
    END
  END f_d[415]
  PIN f_d[416]
    DIRECTION INPUT ;
    USE SIGNAL ;
    PORT
      LAYER M5 ;
        RECT 137.7120 189.9960 137.7360 190.0800 ;
    END
  END f_d[416]
  PIN f_d[417]
    DIRECTION INPUT ;
    USE SIGNAL ;
    PORT
      LAYER M5 ;
        RECT 138.0000 189.9960 138.0240 190.0800 ;
    END
  END f_d[417]
  PIN f_d[418]
    DIRECTION INPUT ;
    USE SIGNAL ;
    PORT
      LAYER M5 ;
        RECT 138.3360 189.9960 138.3600 190.0800 ;
    END
  END f_d[418]
  PIN f_d[419]
    DIRECTION INPUT ;
    USE SIGNAL ;
    PORT
      LAYER M5 ;
        RECT 138.6240 189.9960 138.6480 190.0800 ;
    END
  END f_d[419]
  PIN f_d[420]
    DIRECTION INPUT ;
    USE SIGNAL ;
    PORT
      LAYER M5 ;
        RECT 138.9120 189.9960 138.9360 190.0800 ;
    END
  END f_d[420]
  PIN f_d[421]
    DIRECTION INPUT ;
    USE SIGNAL ;
    PORT
      LAYER M5 ;
        RECT 139.2000 189.9960 139.2240 190.0800 ;
    END
  END f_d[421]
  PIN f_d[422]
    DIRECTION INPUT ;
    USE SIGNAL ;
    PORT
      LAYER M5 ;
        RECT 139.5360 189.9960 139.5600 190.0800 ;
    END
  END f_d[422]
  PIN f_d[423]
    DIRECTION INPUT ;
    USE SIGNAL ;
    PORT
      LAYER M5 ;
        RECT 139.8240 189.9960 139.8480 190.0800 ;
    END
  END f_d[423]
  PIN f_d[424]
    DIRECTION INPUT ;
    USE SIGNAL ;
    PORT
      LAYER M5 ;
        RECT 140.1120 189.9960 140.1360 190.0800 ;
    END
  END f_d[424]
  PIN f_d[425]
    DIRECTION INPUT ;
    USE SIGNAL ;
    PORT
      LAYER M5 ;
        RECT 140.4000 189.9960 140.4240 190.0800 ;
    END
  END f_d[425]
  PIN f_d[426]
    DIRECTION INPUT ;
    USE SIGNAL ;
    PORT
      LAYER M5 ;
        RECT 140.7360 189.9960 140.7600 190.0800 ;
    END
  END f_d[426]
  PIN f_d[427]
    DIRECTION INPUT ;
    USE SIGNAL ;
    PORT
      LAYER M5 ;
        RECT 141.0240 189.9960 141.0480 190.0800 ;
    END
  END f_d[427]
  PIN f_d[428]
    DIRECTION INPUT ;
    USE SIGNAL ;
    PORT
      LAYER M5 ;
        RECT 141.3120 189.9960 141.3360 190.0800 ;
    END
  END f_d[428]
  PIN f_d[429]
    DIRECTION INPUT ;
    USE SIGNAL ;
    PORT
      LAYER M5 ;
        RECT 141.6000 189.9960 141.6240 190.0800 ;
    END
  END f_d[429]
  PIN f_d[430]
    DIRECTION INPUT ;
    USE SIGNAL ;
    PORT
      LAYER M5 ;
        RECT 141.9360 189.9960 141.9600 190.0800 ;
    END
  END f_d[430]
  PIN f_d[431]
    DIRECTION INPUT ;
    USE SIGNAL ;
    PORT
      LAYER M5 ;
        RECT 142.2240 189.9960 142.2480 190.0800 ;
    END
  END f_d[431]
  PIN f_d[432]
    DIRECTION INPUT ;
    USE SIGNAL ;
    PORT
      LAYER M5 ;
        RECT 142.5120 189.9960 142.5360 190.0800 ;
    END
  END f_d[432]
  PIN f_d[433]
    DIRECTION INPUT ;
    USE SIGNAL ;
    PORT
      LAYER M5 ;
        RECT 142.8000 189.9960 142.8240 190.0800 ;
    END
  END f_d[433]
  PIN f_d[434]
    DIRECTION INPUT ;
    USE SIGNAL ;
    PORT
      LAYER M5 ;
        RECT 143.1360 189.9960 143.1600 190.0800 ;
    END
  END f_d[434]
  PIN f_d[435]
    DIRECTION INPUT ;
    USE SIGNAL ;
    PORT
      LAYER M5 ;
        RECT 143.4240 189.9960 143.4480 190.0800 ;
    END
  END f_d[435]
  PIN f_d[436]
    DIRECTION INPUT ;
    USE SIGNAL ;
    PORT
      LAYER M5 ;
        RECT 143.7120 189.9960 143.7360 190.0800 ;
    END
  END f_d[436]
  PIN f_d[437]
    DIRECTION INPUT ;
    USE SIGNAL ;
    PORT
      LAYER M5 ;
        RECT 144.0000 189.9960 144.0240 190.0800 ;
    END
  END f_d[437]
  PIN f_d[438]
    DIRECTION INPUT ;
    USE SIGNAL ;
    PORT
      LAYER M5 ;
        RECT 144.3360 189.9960 144.3600 190.0800 ;
    END
  END f_d[438]
  PIN f_d[439]
    DIRECTION INPUT ;
    USE SIGNAL ;
    PORT
      LAYER M5 ;
        RECT 144.6240 189.9960 144.6480 190.0800 ;
    END
  END f_d[439]
  PIN f_d[440]
    DIRECTION INPUT ;
    USE SIGNAL ;
    PORT
      LAYER M5 ;
        RECT 144.9120 189.9960 144.9360 190.0800 ;
    END
  END f_d[440]
  PIN f_d[441]
    DIRECTION INPUT ;
    USE SIGNAL ;
    PORT
      LAYER M5 ;
        RECT 145.2480 189.9960 145.2720 190.0800 ;
    END
  END f_d[441]
  PIN f_d[442]
    DIRECTION INPUT ;
    USE SIGNAL ;
    PORT
      LAYER M5 ;
        RECT 145.5360 189.9960 145.5600 190.0800 ;
    END
  END f_d[442]
  PIN f_d[443]
    DIRECTION INPUT ;
    USE SIGNAL ;
    PORT
      LAYER M5 ;
        RECT 145.8240 189.9960 145.8480 190.0800 ;
    END
  END f_d[443]
  PIN f_d[444]
    DIRECTION INPUT ;
    USE SIGNAL ;
    PORT
      LAYER M5 ;
        RECT 146.1120 189.9960 146.1360 190.0800 ;
    END
  END f_d[444]
  PIN f_d[445]
    DIRECTION INPUT ;
    USE SIGNAL ;
    PORT
      LAYER M5 ;
        RECT 146.4480 189.9960 146.4720 190.0800 ;
    END
  END f_d[445]
  PIN f_d[446]
    DIRECTION INPUT ;
    USE SIGNAL ;
    PORT
      LAYER M5 ;
        RECT 146.7360 189.9960 146.7600 190.0800 ;
    END
  END f_d[446]
  PIN f_d[447]
    DIRECTION INPUT ;
    USE SIGNAL ;
    PORT
      LAYER M5 ;
        RECT 147.0240 189.9960 147.0480 190.0800 ;
    END
  END f_d[447]
  PIN f_d[448]
    DIRECTION INPUT ;
    USE SIGNAL ;
    PORT
      LAYER M5 ;
        RECT 147.3120 189.9960 147.3360 190.0800 ;
    END
  END f_d[448]
  PIN f_d[449]
    DIRECTION INPUT ;
    USE SIGNAL ;
    PORT
      LAYER M5 ;
        RECT 147.6480 189.9960 147.6720 190.0800 ;
    END
  END f_d[449]
  PIN f_d[450]
    DIRECTION INPUT ;
    USE SIGNAL ;
    PORT
      LAYER M5 ;
        RECT 147.9360 189.9960 147.9600 190.0800 ;
    END
  END f_d[450]
  PIN f_d[451]
    DIRECTION INPUT ;
    USE SIGNAL ;
    PORT
      LAYER M5 ;
        RECT 148.2240 189.9960 148.2480 190.0800 ;
    END
  END f_d[451]
  PIN f_d[452]
    DIRECTION INPUT ;
    USE SIGNAL ;
    PORT
      LAYER M5 ;
        RECT 148.5120 189.9960 148.5360 190.0800 ;
    END
  END f_d[452]
  PIN f_d[453]
    DIRECTION INPUT ;
    USE SIGNAL ;
    PORT
      LAYER M5 ;
        RECT 148.8480 189.9960 148.8720 190.0800 ;
    END
  END f_d[453]
  PIN f_d[454]
    DIRECTION INPUT ;
    USE SIGNAL ;
    PORT
      LAYER M5 ;
        RECT 149.1360 189.9960 149.1600 190.0800 ;
    END
  END f_d[454]
  PIN f_d[455]
    DIRECTION INPUT ;
    USE SIGNAL ;
    PORT
      LAYER M5 ;
        RECT 149.4240 189.9960 149.4480 190.0800 ;
    END
  END f_d[455]
  PIN f_d[456]
    DIRECTION INPUT ;
    USE SIGNAL ;
    PORT
      LAYER M5 ;
        RECT 149.7120 189.9960 149.7360 190.0800 ;
    END
  END f_d[456]
  PIN f_d[457]
    DIRECTION INPUT ;
    USE SIGNAL ;
    PORT
      LAYER M5 ;
        RECT 150.0480 189.9960 150.0720 190.0800 ;
    END
  END f_d[457]
  PIN f_d[458]
    DIRECTION INPUT ;
    USE SIGNAL ;
    PORT
      LAYER M5 ;
        RECT 150.3360 189.9960 150.3600 190.0800 ;
    END
  END f_d[458]
  PIN f_d[459]
    DIRECTION INPUT ;
    USE SIGNAL ;
    PORT
      LAYER M5 ;
        RECT 150.6240 189.9960 150.6480 190.0800 ;
    END
  END f_d[459]
  PIN f_d[460]
    DIRECTION INPUT ;
    USE SIGNAL ;
    PORT
      LAYER M5 ;
        RECT 150.9120 189.9960 150.9360 190.0800 ;
    END
  END f_d[460]
  PIN f_d[461]
    DIRECTION INPUT ;
    USE SIGNAL ;
    PORT
      LAYER M5 ;
        RECT 151.2480 189.9960 151.2720 190.0800 ;
    END
  END f_d[461]
  PIN f_d[462]
    DIRECTION INPUT ;
    USE SIGNAL ;
    PORT
      LAYER M5 ;
        RECT 151.5360 189.9960 151.5600 190.0800 ;
    END
  END f_d[462]
  PIN f_d[463]
    DIRECTION INPUT ;
    USE SIGNAL ;
    PORT
      LAYER M5 ;
        RECT 151.8240 189.9960 151.8480 190.0800 ;
    END
  END f_d[463]
  PIN f_d[464]
    DIRECTION INPUT ;
    USE SIGNAL ;
    PORT
      LAYER M5 ;
        RECT 152.1120 189.9960 152.1360 190.0800 ;
    END
  END f_d[464]
  PIN f_d[465]
    DIRECTION INPUT ;
    USE SIGNAL ;
    PORT
      LAYER M5 ;
        RECT 152.4480 189.9960 152.4720 190.0800 ;
    END
  END f_d[465]
  PIN f_d[466]
    DIRECTION INPUT ;
    USE SIGNAL ;
    PORT
      LAYER M5 ;
        RECT 152.7360 189.9960 152.7600 190.0800 ;
    END
  END f_d[466]
  PIN f_d[467]
    DIRECTION INPUT ;
    USE SIGNAL ;
    PORT
      LAYER M5 ;
        RECT 153.0240 189.9960 153.0480 190.0800 ;
    END
  END f_d[467]
  PIN f_d[468]
    DIRECTION INPUT ;
    USE SIGNAL ;
    PORT
      LAYER M5 ;
        RECT 153.3600 189.9960 153.3840 190.0800 ;
    END
  END f_d[468]
  PIN f_d[469]
    DIRECTION INPUT ;
    USE SIGNAL ;
    PORT
      LAYER M5 ;
        RECT 153.6480 189.9960 153.6720 190.0800 ;
    END
  END f_d[469]
  PIN f_d[470]
    DIRECTION INPUT ;
    USE SIGNAL ;
    PORT
      LAYER M5 ;
        RECT 153.9360 189.9960 153.9600 190.0800 ;
    END
  END f_d[470]
  PIN f_d[471]
    DIRECTION INPUT ;
    USE SIGNAL ;
    PORT
      LAYER M5 ;
        RECT 154.2240 189.9960 154.2480 190.0800 ;
    END
  END f_d[471]
  PIN f_d[472]
    DIRECTION INPUT ;
    USE SIGNAL ;
    PORT
      LAYER M5 ;
        RECT 154.5600 189.9960 154.5840 190.0800 ;
    END
  END f_d[472]
  PIN f_d[473]
    DIRECTION INPUT ;
    USE SIGNAL ;
    PORT
      LAYER M5 ;
        RECT 154.8480 189.9960 154.8720 190.0800 ;
    END
  END f_d[473]
  PIN f_d[474]
    DIRECTION INPUT ;
    USE SIGNAL ;
    PORT
      LAYER M5 ;
        RECT 155.1360 189.9960 155.1600 190.0800 ;
    END
  END f_d[474]
  PIN f_d[475]
    DIRECTION INPUT ;
    USE SIGNAL ;
    PORT
      LAYER M5 ;
        RECT 155.4240 189.9960 155.4480 190.0800 ;
    END
  END f_d[475]
  PIN f_d[476]
    DIRECTION INPUT ;
    USE SIGNAL ;
    PORT
      LAYER M5 ;
        RECT 155.7600 189.9960 155.7840 190.0800 ;
    END
  END f_d[476]
  PIN f_d[477]
    DIRECTION INPUT ;
    USE SIGNAL ;
    PORT
      LAYER M5 ;
        RECT 156.0480 189.9960 156.0720 190.0800 ;
    END
  END f_d[477]
  PIN f_d[478]
    DIRECTION INPUT ;
    USE SIGNAL ;
    PORT
      LAYER M5 ;
        RECT 156.3360 189.9960 156.3600 190.0800 ;
    END
  END f_d[478]
  PIN f_d[479]
    DIRECTION INPUT ;
    USE SIGNAL ;
    PORT
      LAYER M5 ;
        RECT 156.6240 189.9960 156.6480 190.0800 ;
    END
  END f_d[479]
  PIN eps[0]
    DIRECTION INPUT ;
    USE SIGNAL ;
    PORT
      LAYER M5 ;
        RECT 156.9600 189.9960 156.9840 190.0800 ;
    END
  END eps[0]
  PIN eps[1]
    DIRECTION INPUT ;
    USE SIGNAL ;
    PORT
      LAYER M5 ;
        RECT 157.2480 189.9960 157.2720 190.0800 ;
    END
  END eps[1]
  PIN eps[2]
    DIRECTION INPUT ;
    USE SIGNAL ;
    PORT
      LAYER M5 ;
        RECT 157.5360 189.9960 157.5600 190.0800 ;
    END
  END eps[2]
  PIN eps[3]
    DIRECTION INPUT ;
    USE SIGNAL ;
    PORT
      LAYER M5 ;
        RECT 157.8240 189.9960 157.8480 190.0800 ;
    END
  END eps[3]
  PIN eps[4]
    DIRECTION INPUT ;
    USE SIGNAL ;
    PORT
      LAYER M5 ;
        RECT 158.1600 189.9960 158.1840 190.0800 ;
    END
  END eps[4]
  PIN eps[5]
    DIRECTION INPUT ;
    USE SIGNAL ;
    PORT
      LAYER M5 ;
        RECT 158.4480 189.9960 158.4720 190.0800 ;
    END
  END eps[5]
  PIN eps[6]
    DIRECTION INPUT ;
    USE SIGNAL ;
    PORT
      LAYER M5 ;
        RECT 158.7360 189.9960 158.7600 190.0800 ;
    END
  END eps[6]
  PIN eps[7]
    DIRECTION INPUT ;
    USE SIGNAL ;
    PORT
      LAYER M5 ;
        RECT 159.0240 189.9960 159.0480 190.0800 ;
    END
  END eps[7]
  PIN eps[8]
    DIRECTION INPUT ;
    USE SIGNAL ;
    PORT
      LAYER M5 ;
        RECT 159.3600 189.9960 159.3840 190.0800 ;
    END
  END eps[8]
  PIN eps[9]
    DIRECTION INPUT ;
    USE SIGNAL ;
    PORT
      LAYER M5 ;
        RECT 159.6480 189.9960 159.6720 190.0800 ;
    END
  END eps[9]
  PIN eps[10]
    DIRECTION INPUT ;
    USE SIGNAL ;
    PORT
      LAYER M5 ;
        RECT 159.9360 189.9960 159.9600 190.0800 ;
    END
  END eps[10]
  PIN eps[11]
    DIRECTION INPUT ;
    USE SIGNAL ;
    PORT
      LAYER M5 ;
        RECT 160.2240 189.9960 160.2480 190.0800 ;
    END
  END eps[11]
  PIN eps[12]
    DIRECTION INPUT ;
    USE SIGNAL ;
    PORT
      LAYER M5 ;
        RECT 160.5600 189.9960 160.5840 190.0800 ;
    END
  END eps[12]
  PIN eps[13]
    DIRECTION INPUT ;
    USE SIGNAL ;
    PORT
      LAYER M5 ;
        RECT 160.8480 189.9960 160.8720 190.0800 ;
    END
  END eps[13]
  PIN eps[14]
    DIRECTION INPUT ;
    USE SIGNAL ;
    PORT
      LAYER M5 ;
        RECT 161.1360 189.9960 161.1600 190.0800 ;
    END
  END eps[14]
  PIN eps[15]
    DIRECTION INPUT ;
    USE SIGNAL ;
    PORT
      LAYER M5 ;
        RECT 161.4720 189.9960 161.4960 190.0800 ;
    END
  END eps[15]
  PIN eps[16]
    DIRECTION INPUT ;
    USE SIGNAL ;
    PORT
      LAYER M5 ;
        RECT 161.7600 189.9960 161.7840 190.0800 ;
    END
  END eps[16]
  PIN eps[17]
    DIRECTION INPUT ;
    USE SIGNAL ;
    PORT
      LAYER M5 ;
        RECT 162.0480 189.9960 162.0720 190.0800 ;
    END
  END eps[17]
  PIN eps[18]
    DIRECTION INPUT ;
    USE SIGNAL ;
    PORT
      LAYER M5 ;
        RECT 162.3360 189.9960 162.3600 190.0800 ;
    END
  END eps[18]
  PIN eps[19]
    DIRECTION INPUT ;
    USE SIGNAL ;
    PORT
      LAYER M5 ;
        RECT 162.6720 189.9960 162.6960 190.0800 ;
    END
  END eps[19]
  PIN eps[20]
    DIRECTION INPUT ;
    USE SIGNAL ;
    PORT
      LAYER M5 ;
        RECT 162.9600 189.9960 162.9840 190.0800 ;
    END
  END eps[20]
  PIN eps[21]
    DIRECTION INPUT ;
    USE SIGNAL ;
    PORT
      LAYER M5 ;
        RECT 163.2480 189.9960 163.2720 190.0800 ;
    END
  END eps[21]
  PIN eps[22]
    DIRECTION INPUT ;
    USE SIGNAL ;
    PORT
      LAYER M5 ;
        RECT 163.5360 189.9960 163.5600 190.0800 ;
    END
  END eps[22]
  PIN eps[23]
    DIRECTION INPUT ;
    USE SIGNAL ;
    PORT
      LAYER M5 ;
        RECT 163.8720 189.9960 163.8960 190.0800 ;
    END
  END eps[23]
  PIN eps[24]
    DIRECTION INPUT ;
    USE SIGNAL ;
    PORT
      LAYER M5 ;
        RECT 164.1600 189.9960 164.1840 190.0800 ;
    END
  END eps[24]
  PIN eps[25]
    DIRECTION INPUT ;
    USE SIGNAL ;
    PORT
      LAYER M5 ;
        RECT 164.4480 189.9960 164.4720 190.0800 ;
    END
  END eps[25]
  PIN eps[26]
    DIRECTION INPUT ;
    USE SIGNAL ;
    PORT
      LAYER M5 ;
        RECT 164.7360 189.9960 164.7600 190.0800 ;
    END
  END eps[26]
  PIN eps[27]
    DIRECTION INPUT ;
    USE SIGNAL ;
    PORT
      LAYER M5 ;
        RECT 165.0720 189.9960 165.0960 190.0800 ;
    END
  END eps[27]
  PIN eps[28]
    DIRECTION INPUT ;
    USE SIGNAL ;
    PORT
      LAYER M5 ;
        RECT 165.3600 189.9960 165.3840 190.0800 ;
    END
  END eps[28]
  PIN eps[29]
    DIRECTION INPUT ;
    USE SIGNAL ;
    PORT
      LAYER M5 ;
        RECT 165.6480 189.9960 165.6720 190.0800 ;
    END
  END eps[29]
  PIN eps[30]
    DIRECTION INPUT ;
    USE SIGNAL ;
    PORT
      LAYER M5 ;
        RECT 165.9360 189.9960 165.9600 190.0800 ;
    END
  END eps[30]
  PIN eps[31]
    DIRECTION INPUT ;
    USE SIGNAL ;
    PORT
      LAYER M5 ;
        RECT 166.2720 189.9960 166.2960 190.0800 ;
    END
  END eps[31]
  PIN clk
    DIRECTION INPUT ;
    USE SIGNAL ;
    PORT
      LAYER M5 ;
        RECT 166.5480 189.6000 166.5960 190.0800 ;
    END
  END clk
  PIN rst_n
    DIRECTION INPUT ;
    USE SIGNAL ;
    PORT
      LAYER M5 ;
        RECT 166.8480 189.9960 166.8720 190.0800 ;
    END
  END rst_n
  PIN r_v
    DIRECTION OUTPUT ;
    USE SIGNAL ;
    PORT
      LAYER M5 ;
        RECT 167.1360 189.9960 167.1600 190.0800 ;
    END
  END r_v
  PIN r[0]
    DIRECTION OUTPUT ;
    USE SIGNAL ;
    PORT
      LAYER M5 ;
        RECT 167.4720 189.9960 167.4960 190.0800 ;
    END
  END r[0]
  PIN r[1]
    DIRECTION OUTPUT ;
    USE SIGNAL ;
    PORT
      LAYER M5 ;
        RECT 167.7600 189.9960 167.7840 190.0800 ;
    END
  END r[1]
  PIN r[2]
    DIRECTION OUTPUT ;
    USE SIGNAL ;
    PORT
      LAYER M5 ;
        RECT 168.0480 189.9960 168.0720 190.0800 ;
    END
  END r[2]
  PIN r[3]
    DIRECTION OUTPUT ;
    USE SIGNAL ;
    PORT
      LAYER M5 ;
        RECT 168.3360 189.9960 168.3600 190.0800 ;
    END
  END r[3]
  PIN r[4]
    DIRECTION OUTPUT ;
    USE SIGNAL ;
    PORT
      LAYER M5 ;
        RECT 168.6720 189.9960 168.6960 190.0800 ;
    END
  END r[4]
  PIN r[5]
    DIRECTION OUTPUT ;
    USE SIGNAL ;
    PORT
      LAYER M5 ;
        RECT 168.9600 189.9960 168.9840 190.0800 ;
    END
  END r[5]
  PIN r[6]
    DIRECTION OUTPUT ;
    USE SIGNAL ;
    PORT
      LAYER M5 ;
        RECT 169.2480 189.9960 169.2720 190.0800 ;
    END
  END r[6]
  PIN r[7]
    DIRECTION OUTPUT ;
    USE SIGNAL ;
    PORT
      LAYER M5 ;
        RECT 169.5840 189.9960 169.6080 190.0800 ;
    END
  END r[7]
  PIN r[8]
    DIRECTION OUTPUT ;
    USE SIGNAL ;
    PORT
      LAYER M5 ;
        RECT 169.8720 189.9960 169.8960 190.0800 ;
    END
  END r[8]
  PIN r[9]
    DIRECTION OUTPUT ;
    USE SIGNAL ;
    PORT
      LAYER M5 ;
        RECT 170.1600 189.9960 170.1840 190.0800 ;
    END
  END r[9]
  PIN r[10]
    DIRECTION OUTPUT ;
    USE SIGNAL ;
    PORT
      LAYER M5 ;
        RECT 170.4480 189.9960 170.4720 190.0800 ;
    END
  END r[10]
  PIN r[11]
    DIRECTION OUTPUT ;
    USE SIGNAL ;
    PORT
      LAYER M5 ;
        RECT 170.7840 189.9960 170.8080 190.0800 ;
    END
  END r[11]
  PIN r[12]
    DIRECTION OUTPUT ;
    USE SIGNAL ;
    PORT
      LAYER M5 ;
        RECT 171.0720 189.9960 171.0960 190.0800 ;
    END
  END r[12]
  PIN r[13]
    DIRECTION OUTPUT ;
    USE SIGNAL ;
    PORT
      LAYER M5 ;
        RECT 171.3600 189.9960 171.3840 190.0800 ;
    END
  END r[13]
  PIN r[14]
    DIRECTION OUTPUT ;
    USE SIGNAL ;
    PORT
      LAYER M5 ;
        RECT 171.6480 189.9960 171.6720 190.0800 ;
    END
  END r[14]
  PIN r[15]
    DIRECTION OUTPUT ;
    USE SIGNAL ;
    PORT
      LAYER M5 ;
        RECT 171.9840 189.9960 172.0080 190.0800 ;
    END
  END r[15]
  PIN r[16]
    DIRECTION OUTPUT ;
    USE SIGNAL ;
    PORT
      LAYER M5 ;
        RECT 172.2720 189.9960 172.2960 190.0800 ;
    END
  END r[16]
  PIN r[17]
    DIRECTION OUTPUT ;
    USE SIGNAL ;
    PORT
      LAYER M5 ;
        RECT 172.5600 189.9960 172.5840 190.0800 ;
    END
  END r[17]
  PIN r[18]
    DIRECTION OUTPUT ;
    USE SIGNAL ;
    PORT
      LAYER M5 ;
        RECT 172.8480 189.9960 172.8720 190.0800 ;
    END
  END r[18]
  PIN r[19]
    DIRECTION OUTPUT ;
    USE SIGNAL ;
    PORT
      LAYER M5 ;
        RECT 173.1840 189.9960 173.2080 190.0800 ;
    END
  END r[19]
  PIN r[20]
    DIRECTION OUTPUT ;
    USE SIGNAL ;
    PORT
      LAYER M5 ;
        RECT 173.4720 189.9960 173.4960 190.0800 ;
    END
  END r[20]
  PIN r[21]
    DIRECTION OUTPUT ;
    USE SIGNAL ;
    PORT
      LAYER M5 ;
        RECT 173.7600 189.9960 173.7840 190.0800 ;
    END
  END r[21]
  PIN r[22]
    DIRECTION OUTPUT ;
    USE SIGNAL ;
    PORT
      LAYER M5 ;
        RECT 174.0480 189.9960 174.0720 190.0800 ;
    END
  END r[22]
  PIN r[23]
    DIRECTION OUTPUT ;
    USE SIGNAL ;
    PORT
      LAYER M5 ;
        RECT 174.3840 189.9960 174.4080 190.0800 ;
    END
  END r[23]
  PIN r[24]
    DIRECTION OUTPUT ;
    USE SIGNAL ;
    PORT
      LAYER M5 ;
        RECT 174.6720 189.9960 174.6960 190.0800 ;
    END
  END r[24]
  PIN r[25]
    DIRECTION OUTPUT ;
    USE SIGNAL ;
    PORT
      LAYER M5 ;
        RECT 174.9600 189.9960 174.9840 190.0800 ;
    END
  END r[25]
  PIN r[26]
    DIRECTION OUTPUT ;
    USE SIGNAL ;
    PORT
      LAYER M5 ;
        RECT 175.2480 189.9960 175.2720 190.0800 ;
    END
  END r[26]
  PIN r[27]
    DIRECTION OUTPUT ;
    USE SIGNAL ;
    PORT
      LAYER M5 ;
        RECT 175.5840 189.9960 175.6080 190.0800 ;
    END
  END r[27]
  PIN r[28]
    DIRECTION OUTPUT ;
    USE SIGNAL ;
    PORT
      LAYER M5 ;
        RECT 175.8720 189.9960 175.8960 190.0800 ;
    END
  END r[28]
  PIN r[29]
    DIRECTION OUTPUT ;
    USE SIGNAL ;
    PORT
      LAYER M5 ;
        RECT 176.1600 189.9960 176.1840 190.0800 ;
    END
  END r[29]
  PIN r[30]
    DIRECTION OUTPUT ;
    USE SIGNAL ;
    PORT
      LAYER M5 ;
        RECT 176.4480 189.9960 176.4720 190.0800 ;
    END
  END r[30]
  PIN r[31]
    DIRECTION OUTPUT ;
    USE SIGNAL ;
    PORT
      LAYER M5 ;
        RECT 176.7840 189.9960 176.8080 190.0800 ;
    END
  END r[31]
  PIN fault
    DIRECTION OUTPUT ;
    USE SIGNAL ;
    PORT
      LAYER M5 ;
        RECT 177.0720 189.9960 177.0960 190.0800 ;
    END
  END fault
END ot_s81dv_norm_finish
END LIBRARY
